VERSION 5.7 ;
NAMESCASESENSITIVE ON ;
BUSBITCHARS "[]" ;
DIVIDERCHAR "|" ;

PROPERTYDEFINITIONS
    LAYER LEF58_TYPE STRING ;
END PROPERTYDEFINITIONS


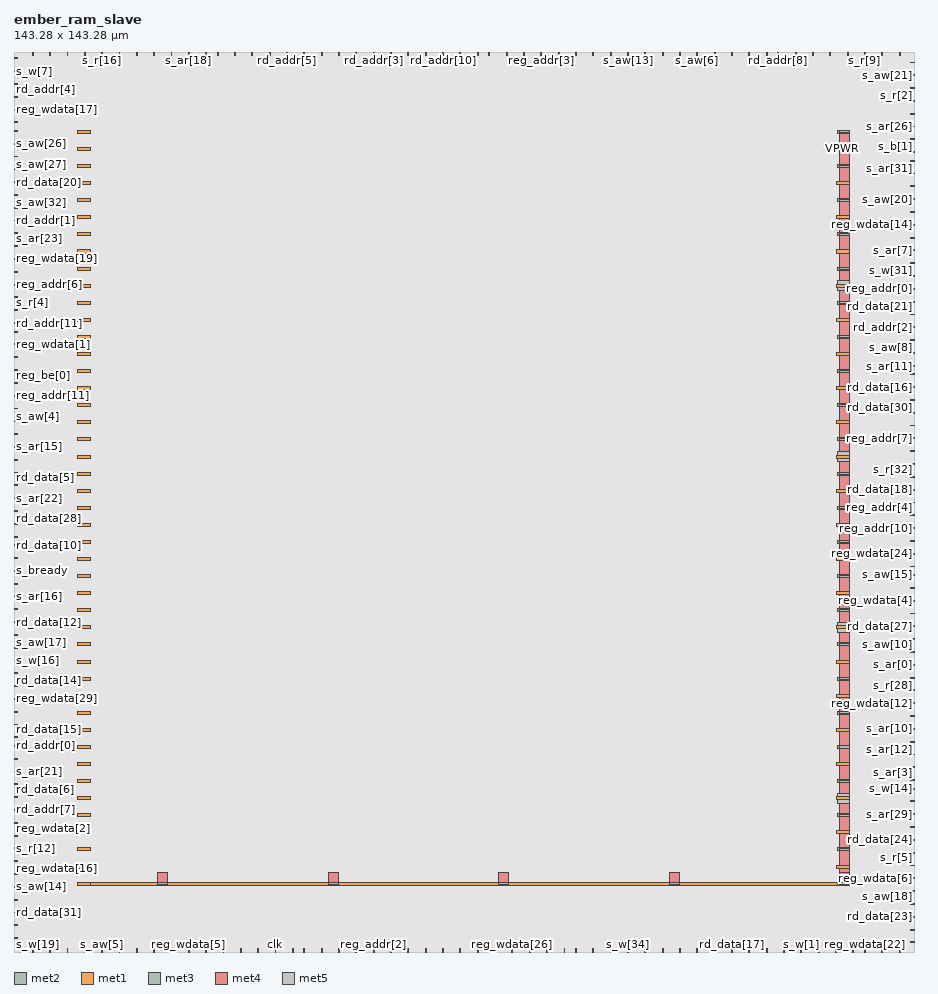
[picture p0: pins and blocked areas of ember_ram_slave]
MACRO ember_ram_slave
    CLASS BLOCK ;
    SIZE 143.28 BY 143.28 ;
    SYMMETRY Y ;
    PIN clk
        DIRECTION INPUT ; 
        USE SIGNAL ; 
        PORT
            LAYER met2 ;
              RECT  41.56 0 41.7 0.485 ;
        END
    END clk
    PIN rd_addr[0]
        DIRECTION OUTPUT ; 
        USE SIGNAL ; 
        PORT
            LAYER met1 ;
              RECT  0 32.74 0.595 32.88 ;
        END
    END rd_addr[0]
    PIN rd_addr[10]
        DIRECTION OUTPUT ; 
        USE SIGNAL ; 
        PORT
            LAYER met2 ;
              RECT  68.24 142.795 68.38 143.28 ;
        END
    END rd_addr[10]
    PIN rd_addr[11]
        DIRECTION OUTPUT ; 
        USE SIGNAL ; 
        PORT
            LAYER met1 ;
              RECT  0 100.06 0.595 100.2 ;
        END
    END rd_addr[11]
    PIN rd_addr[1]
        DIRECTION OUTPUT ; 
        USE SIGNAL ; 
        PORT
            LAYER met1 ;
              RECT  0 116.38 0.595 116.52 ;
        END
    END rd_addr[1]
    PIN rd_addr[2]
        DIRECTION OUTPUT ; 
        USE SIGNAL ; 
        PORT
            LAYER met1 ;
              RECT  142.685 99.38 143.28 99.52 ;
        END
    END rd_addr[2]
    PIN rd_addr[3]
        DIRECTION OUTPUT ; 
        USE SIGNAL ; 
        PORT
            LAYER met2 ;
              RECT  57.2 142.795 57.34 143.28 ;
        END
    END rd_addr[3]
    PIN rd_addr[4]
        DIRECTION OUTPUT ; 
        USE SIGNAL ; 
        PORT
            LAYER met1 ;
              RECT  0 136.1 0.595 136.24 ;
        END
    END rd_addr[4]
    PIN rd_addr[5]
        DIRECTION OUTPUT ; 
        USE SIGNAL ; 
        PORT
            LAYER met2 ;
              RECT  43.4 142.795 43.54 143.28 ;
        END
    END rd_addr[5]
    PIN rd_addr[6]
        DIRECTION OUTPUT ; 
        USE SIGNAL ; 
        PORT
            LAYER met1 ;
              RECT  142.685 141.54 143.28 141.68 ;
        END
    END rd_addr[6]
    PIN rd_addr[7]
        DIRECTION OUTPUT ; 
        USE SIGNAL ; 
        PORT
            LAYER met1 ;
              RECT  0 22.54 0.595 22.68 ;
        END
    END rd_addr[7]
    PIN rd_addr[8]
        DIRECTION OUTPUT ; 
        USE SIGNAL ; 
        PORT
            LAYER met2 ;
              RECT  121.6 142.795 121.74 143.28 ;
        END
    END rd_addr[8]
    PIN rd_addr[9]
        DIRECTION OUTPUT ; 
        USE SIGNAL ; 
        PORT
            LAYER met2 ;
              RECT  65.48 142.795 65.62 143.28 ;
        END
    END rd_addr[9]
    PIN rd_data[0]
        DIRECTION INPUT ; 
        USE SIGNAL ; 
        PORT
            LAYER met2 ;
              RECT  8.44 0 8.58 0.485 ;
        END
    END rd_data[0]
    PIN rd_data[10]
        DIRECTION INPUT ; 
        USE SIGNAL ; 
        PORT
            LAYER met1 ;
              RECT  0 64.7 0.595 64.84 ;
        END
    END rd_data[10]
    PIN rd_data[11]
        DIRECTION INPUT ; 
        USE SIGNAL ; 
        PORT
            LAYER met2 ;
              RECT  2.92 142.795 3.06 143.28 ;
        END
    END rd_data[11]
    PIN rd_data[12]
        DIRECTION INPUT ; 
        USE SIGNAL ; 
        PORT
            LAYER met1 ;
              RECT  0 52.46 0.595 52.6 ;
        END
    END rd_data[12]
    PIN rd_data[13]
        DIRECTION INPUT ; 
        USE SIGNAL ; 
        PORT
            LAYER met2 ;
              RECT  62.72 142.795 62.86 143.28 ;
        END
    END rd_data[13]
    PIN rd_data[14]
        DIRECTION INPUT ; 
        USE SIGNAL ; 
        PORT
            LAYER met1 ;
              RECT  0 44.3 0.595 44.44 ;
        END
    END rd_data[14]
    PIN rd_data[15]
        DIRECTION INPUT ; 
        USE SIGNAL ; 
        PORT
            LAYER met1 ;
              RECT  0 34.1 0.595 34.24 ;
        END
    END rd_data[15]
    PIN rd_data[16]
        DIRECTION INPUT ; 
        USE SIGNAL ; 
        PORT
            LAYER met1 ;
              RECT  142.685 89.86 143.28 90 ;
        END
    END rd_data[16]
    PIN rd_data[17]
        DIRECTION INPUT ; 
        USE SIGNAL ; 
        PORT
            LAYER met2 ;
              RECT  114.24 0 114.38 0.485 ;
        END
    END rd_data[17]
    PIN rd_data[18]
        DIRECTION INPUT ; 
        USE SIGNAL ; 
        PORT
            LAYER met1 ;
              RECT  142.685 73.54 143.28 73.68 ;
        END
    END rd_data[18]
    PIN rd_data[19]
        DIRECTION INPUT ; 
        USE SIGNAL ; 
        PORT
            LAYER met2 ;
              RECT  5.68 142.795 5.82 143.28 ;
        END
    END rd_data[19]
    PIN rd_data[1]
        DIRECTION INPUT ; 
        USE SIGNAL ; 
        PORT
            LAYER met2 ;
              RECT  78.36 142.795 78.5 143.28 ;
        END
    END rd_data[1]
    PIN rd_data[20]
        DIRECTION INPUT ; 
        USE SIGNAL ; 
        PORT
            LAYER met1 ;
              RECT  0 122.5 0.595 122.64 ;
        END
    END rd_data[20]
    PIN rd_data[21]
        DIRECTION INPUT ; 
        USE SIGNAL ; 
        PORT
            LAYER met1 ;
              RECT  142.685 101.42 143.28 101.56 ;
        END
    END rd_data[21]
    PIN rd_data[22]
        DIRECTION INPUT ; 
        USE SIGNAL ; 
        PORT
            LAYER met2 ;
              RECT  25 142.795 25.14 143.28 ;
        END
    END rd_data[22]
    PIN rd_data[23]
        DIRECTION INPUT ; 
        USE SIGNAL ; 
        PORT
            LAYER met1 ;
              RECT  142.685 5.54 143.28 5.68 ;
        END
    END rd_data[23]
    PIN rd_data[24]
        DIRECTION INPUT ; 
        USE SIGNAL ; 
        PORT
            LAYER met1 ;
              RECT  142.685 17.78 143.28 17.92 ;
        END
    END rd_data[24]
    PIN rd_data[25]
        DIRECTION INPUT ; 
        USE SIGNAL ; 
        PORT
            LAYER met2 ;
              RECT  32.36 142.795 32.5 143.28 ;
        END
    END rd_data[25]
    PIN rd_data[26]
        DIRECTION INPUT ; 
        USE SIGNAL ; 
        PORT
            LAYER met1 ;
              RECT  0 2.14 0.595 2.28 ;
        END
    END rd_data[26]
    PIN rd_data[27]
        DIRECTION INPUT ; 
        USE SIGNAL ; 
        PORT
            LAYER met1 ;
              RECT  142.685 51.78 143.28 51.92 ;
        END
    END rd_data[27]
    PIN rd_data[28]
        DIRECTION INPUT ; 
        USE SIGNAL ; 
        PORT
            LAYER met1 ;
              RECT  0 70.14 0.595 70.28 ;
        END
    END rd_data[28]
    PIN rd_data[29]
        DIRECTION INPUT ; 
        USE SIGNAL ; 
        PORT
            LAYER met1 ;
              RECT  142.685 9.62 143.28 9.76 ;
        END
    END rd_data[29]
    PIN rd_data[2]
        DIRECTION INPUT ; 
        USE SIGNAL ; 
        PORT
            LAYER met2 ;
              RECT  35.12 142.795 35.26 143.28 ;
        END
    END rd_data[2]
    PIN rd_data[30]
        DIRECTION INPUT ; 
        USE SIGNAL ; 
        PORT
            LAYER met1 ;
              RECT  142.685 87.82 143.28 87.96 ;
        END
    END rd_data[30]
    PIN rd_data[31]
        DIRECTION INPUT ; 
        USE SIGNAL ; 
        PORT
            LAYER met1 ;
              RECT  0 6.22 0.595 6.36 ;
        END
    END rd_data[31]
    PIN rd_data[3]
        DIRECTION INPUT ; 
        USE SIGNAL ; 
        PORT
            LAYER met2 ;
              RECT  94.92 0 95.06 0.485 ;
        END
    END rd_data[3]
    PIN rd_data[4]
        DIRECTION INPUT ; 
        USE SIGNAL ; 
        PORT
            LAYER met2 ;
              RECT  105.96 142.795 106.1 143.28 ;
        END
    END rd_data[4]
    PIN rd_data[5]
        DIRECTION INPUT ; 
        USE SIGNAL ; 
        PORT
            LAYER met1 ;
              RECT  0 74.22 0.595 74.36 ;
        END
    END rd_data[5]
    PIN rd_data[6]
        DIRECTION INPUT ; 
        USE SIGNAL ; 
        PORT
            LAYER met1 ;
              RECT  0 24.58 0.595 24.72 ;
        END
    END rd_data[6]
    PIN rd_data[7]
        DIRECTION INPUT ; 
        USE SIGNAL ; 
        PORT
            LAYER met1 ;
              RECT  0 26.62 0.595 26.76 ;
        END
    END rd_data[7]
    PIN rd_data[8]
        DIRECTION INPUT ; 
        USE SIGNAL ; 
        PORT
            LAYER met2 ;
              RECT  54.44 142.795 54.58 143.28 ;
        END
    END rd_data[8]
    PIN rd_data[9]
        DIRECTION INPUT ; 
        USE SIGNAL ; 
        PORT
            LAYER met1 ;
              RECT  142.685 127.26 143.28 127.4 ;
        END
    END rd_data[9]
    PIN reg_addr[0]
        DIRECTION OUTPUT ; 
        USE SIGNAL ; 
        PORT
            LAYER met1 ;
              RECT  142.685 105.5 143.28 105.64 ;
        END
    END reg_addr[0]
    PIN reg_addr[10]
        DIRECTION OUTPUT ; 
        USE SIGNAL ; 
        PORT
            LAYER met1 ;
              RECT  142.685 67.42 143.28 67.56 ;
        END
    END reg_addr[10]
    PIN reg_addr[11]
        DIRECTION OUTPUT ; 
        USE SIGNAL ; 
        PORT
            LAYER met1 ;
              RECT  0 88.5 0.595 88.64 ;
        END
    END reg_addr[11]
    PIN reg_addr[1]
        DIRECTION OUTPUT ; 
        USE SIGNAL ; 
        PORT
            LAYER met2 ;
              RECT  138.16 0 138.3 0.485 ;
        END
    END reg_addr[1]
    PIN reg_addr[2]
        DIRECTION OUTPUT ; 
        USE SIGNAL ; 
        PORT
            LAYER met2 ;
              RECT  57.2 0 57.34 0.485 ;
        END
    END reg_addr[2]
    PIN reg_addr[3]
        DIRECTION OUTPUT ; 
        USE SIGNAL ; 
        PORT
            LAYER met2 ;
              RECT  83.88 142.795 84.02 143.28 ;
        END
    END reg_addr[3]
    PIN reg_addr[4]
        DIRECTION OUTPUT ; 
        USE SIGNAL ; 
        PORT
            LAYER met1 ;
              RECT  142.685 69.46 143.28 69.6 ;
        END
    END reg_addr[4]
    PIN reg_addr[5]
        DIRECTION OUTPUT ; 
        USE SIGNAL ; 
        PORT
            LAYER met2 ;
              RECT  59.96 0 60.1 0.485 ;
        END
    END reg_addr[5]
    PIN reg_addr[6]
        DIRECTION OUTPUT ; 
        USE SIGNAL ; 
        PORT
            LAYER met1 ;
              RECT  0 106.18 0.595 106.32 ;
        END
    END reg_addr[6]
    PIN reg_addr[7]
        DIRECTION OUTPUT ; 
        USE SIGNAL ; 
        PORT
            LAYER met1 ;
              RECT  142.685 81.7 143.28 81.84 ;
        END
    END reg_addr[7]
    PIN reg_addr[8]
        DIRECTION OUTPUT ; 
        USE SIGNAL ; 
        PORT
            LAYER met2 ;
              RECT  8.44 142.795 8.58 143.28 ;
        END
    END reg_addr[8]
    PIN reg_addr[9]
        DIRECTION OUTPUT ; 
        USE SIGNAL ; 
        PORT
            LAYER met2 ;
              RECT  51.68 142.795 51.82 143.28 ;
        END
    END reg_addr[9]
    PIN reg_be[0]
        DIRECTION OUTPUT ; 
        USE SIGNAL ; 
        PORT
            LAYER met1 ;
              RECT  0 90.54 0.595 90.68 ;
        END
    END reg_be[0]
    PIN reg_be[1]
        DIRECTION OUTPUT ; 
        USE SIGNAL ; 
        PORT
            LAYER met2 ;
              RECT  132.64 142.795 132.78 143.28 ;
        END
    END reg_be[1]
    PIN reg_be[2]
        DIRECTION OUTPUT ; 
        USE SIGNAL ; 
        PORT
            LAYER met2 ;
              RECT  38.8 0 38.94 0.485 ;
        END
    END reg_be[2]
    PIN reg_be[3]
        DIRECTION OUTPUT ; 
        USE SIGNAL ; 
        PORT
            LAYER met2 ;
              RECT  92.16 0 92.3 0.485 ;
        END
    END reg_be[3]
    PIN reg_wdata[0]
        DIRECTION OUTPUT ; 
        USE SIGNAL ; 
        PORT
            LAYER met2 ;
              RECT  111.48 142.795 111.62 143.28 ;
        END
    END reg_wdata[0]
    PIN reg_wdata[10]
        DIRECTION OUTPUT ; 
        USE SIGNAL ; 
        PORT
            LAYER met2 ;
              RECT  128.04 0 128.18 0.485 ;
        END
    END reg_wdata[10]
    PIN reg_wdata[11]
        DIRECTION OUTPUT ; 
        USE SIGNAL ; 
        PORT
            LAYER met2 ;
              RECT  22.24 142.795 22.38 143.28 ;
        END
    END reg_wdata[11]
    PIN reg_wdata[12]
        DIRECTION OUTPUT ; 
        USE SIGNAL ; 
        PORT
            LAYER met1 ;
              RECT  142.685 39.54 143.28 39.68 ;
        END
    END reg_wdata[12]
    PIN reg_wdata[13]
        DIRECTION OUTPUT ; 
        USE SIGNAL ; 
        PORT
            LAYER met1 ;
              RECT  0 142.22 0.595 142.36 ;
        END
    END reg_wdata[13]
    PIN reg_wdata[14]
        DIRECTION OUTPUT ; 
        USE SIGNAL ; 
        PORT
            LAYER met1 ;
              RECT  142.685 115.7 143.28 115.84 ;
        END
    END reg_wdata[14]
    PIN reg_wdata[15]
        DIRECTION OUTPUT ; 
        USE SIGNAL ; 
        PORT
            LAYER met2 ;
              RECT  119.76 142.795 119.9 143.28 ;
        END
    END reg_wdata[15]
    PIN reg_wdata[16]
        DIRECTION OUTPUT ; 
        USE SIGNAL ; 
        PORT
            LAYER met1 ;
              RECT  0 14.38 0.595 14.52 ;
        END
    END reg_wdata[16]
    PIN reg_wdata[17]
        DIRECTION OUTPUT ; 
        USE SIGNAL ; 
        PORT
            LAYER met1 ;
              RECT  0 134.06 0.595 134.2 ;
        END
    END reg_wdata[17]
    PIN reg_wdata[18]
        DIRECTION OUTPUT ; 
        USE SIGNAL ; 
        PORT
            LAYER met2 ;
              RECT  46.16 142.795 46.3 143.28 ;
        END
    END reg_wdata[18]
    PIN reg_wdata[19]
        DIRECTION OUTPUT ; 
        USE SIGNAL ; 
        PORT
            LAYER met1 ;
              RECT  0 110.26 0.595 110.4 ;
        END
    END reg_wdata[19]
    PIN reg_wdata[1]
        DIRECTION OUTPUT ; 
        USE SIGNAL ; 
        PORT
            LAYER met1 ;
              RECT  0 96.66 0.595 96.8 ;
        END
    END reg_wdata[1]
    PIN reg_wdata[20]
        DIRECTION OUTPUT ; 
        USE SIGNAL ; 
        PORT
            LAYER met1 ;
              RECT  142.685 135.42 143.28 135.56 ;
        END
    END reg_wdata[20]
    PIN reg_wdata[21]
        DIRECTION OUTPUT ; 
        USE SIGNAL ; 
        PORT
            LAYER met1 ;
              RECT  142.685 3.5 143.28 3.64 ;
        END
    END reg_wdata[21]
    PIN reg_wdata[22]
        DIRECTION OUTPUT ; 
        USE SIGNAL ; 
        PORT
            LAYER met2 ;
              RECT  135.4 0 135.54 0.485 ;
        END
    END reg_wdata[22]
    PIN reg_wdata[23]
        DIRECTION OUTPUT ; 
        USE SIGNAL ; 
        PORT
            LAYER met2 ;
              RECT  68.24 0 68.38 0.485 ;
        END
    END reg_wdata[23]
    PIN reg_wdata[24]
        DIRECTION OUTPUT ; 
        USE SIGNAL ; 
        PORT
            LAYER met1 ;
              RECT  142.685 63.34 143.28 63.48 ;
        END
    END reg_wdata[24]
    PIN reg_wdata[25]
        DIRECTION OUTPUT ; 
        USE SIGNAL ; 
        PORT
            LAYER met2 ;
              RECT  65.48 0 65.62 0.485 ;
        END
    END reg_wdata[25]
    PIN reg_wdata[26]
        DIRECTION OUTPUT ; 
        USE SIGNAL ; 
        PORT
            LAYER met2 ;
              RECT  79.28 0 79.42 0.485 ;
        END
    END reg_wdata[26]
    PIN reg_wdata[27]
        DIRECTION OUTPUT ; 
        USE SIGNAL ; 
        PORT
            LAYER met1 ;
              RECT  0 68.1 0.595 68.24 ;
        END
    END reg_wdata[27]
    PIN reg_wdata[28]
        DIRECTION OUTPUT ; 
        USE SIGNAL ; 
        PORT
            LAYER met2 ;
              RECT  19.48 0 19.62 0.485 ;
        END
    END reg_wdata[28]
    PIN reg_wdata[29]
        DIRECTION OUTPUT ; 
        USE SIGNAL ; 
        PORT
            LAYER met1 ;
              RECT  0 40.22 0.595 40.36 ;
        END
    END reg_wdata[29]
    PIN reg_wdata[2]
        DIRECTION OUTPUT ; 
        USE SIGNAL ; 
        PORT
            LAYER met1 ;
              RECT  0 18.46 0.595 18.6 ;
        END
    END reg_wdata[2]
    PIN reg_wdata[30]
        DIRECTION OUTPUT ; 
        USE SIGNAL ; 
        PORT
            LAYER met2 ;
              RECT  140.92 0 141.06 0.485 ;
        END
    END reg_wdata[30]
    PIN reg_wdata[31]
        DIRECTION OUTPUT ; 
        USE SIGNAL ; 
        PORT
            LAYER met2 ;
              RECT  138.16 142.795 138.3 143.28 ;
        END
    END reg_wdata[31]
    PIN reg_wdata[3]
        DIRECTION OUTPUT ; 
        USE SIGNAL ; 
        PORT
            LAYER met1 ;
              RECT  142.685 85.78 143.28 85.92 ;
        END
    END reg_wdata[3]
    PIN reg_wdata[4]
        DIRECTION OUTPUT ; 
        USE SIGNAL ; 
        PORT
            LAYER met1 ;
              RECT  142.685 55.86 143.28 56 ;
        END
    END reg_wdata[4]
    PIN reg_wdata[5]
        DIRECTION OUTPUT ; 
        USE SIGNAL ; 
        PORT
            LAYER met2 ;
              RECT  27.76 0 27.9 0.485 ;
        END
    END reg_wdata[5]
    PIN reg_wdata[6]
        DIRECTION OUTPUT ; 
        USE SIGNAL ; 
        PORT
            LAYER met1 ;
              RECT  142.685 11.66 143.28 11.8 ;
        END
    END reg_wdata[6]
    PIN reg_wdata[7]
        DIRECTION OUTPUT ; 
        USE SIGNAL ; 
        PORT
            LAYER met1 ;
              RECT  142.685 133.38 143.28 133.52 ;
        END
    END reg_wdata[7]
    PIN reg_wdata[8]
        DIRECTION OUTPUT ; 
        USE SIGNAL ; 
        PORT
            LAYER met2 ;
              RECT  73.76 142.795 73.9 143.28 ;
        END
    END reg_wdata[8]
    PIN reg_wdata[9]
        DIRECTION OUTPUT ; 
        USE SIGNAL ; 
        PORT
            LAYER met2 ;
              RECT  16.72 0 16.86 0.485 ;
        END
    END reg_wdata[9]
    PIN reg_wr_en
        DIRECTION OUTPUT ; 
        USE SIGNAL ; 
        PORT
            LAYER met2 ;
              RECT  94.92 142.795 95.06 143.28 ;
        END
    END reg_wr_en
    PIN rst_n
        DIRECTION INPUT ; 
        USE SIGNAL ; 
        PORT
            LAYER met1 ;
              RECT  0 94.62 0.595 94.76 ;
        END
    END rst_n
    PIN s_ar[0]
        DIRECTION INPUT ; 
        USE SIGNAL ; 
        PORT
            LAYER met1 ;
              RECT  142.685 45.66 143.28 45.8 ;
        END
    END s_ar[0]
    PIN s_ar[10]
        DIRECTION INPUT ; 
        USE SIGNAL ; 
        PORT
            LAYER met1 ;
              RECT  142.685 35.46 143.28 35.6 ;
        END
    END s_ar[10]
    PIN s_ar[11]
        DIRECTION INPUT ; 
        USE SIGNAL ; 
        PORT
            LAYER met1 ;
              RECT  142.685 91.9 143.28 92.04 ;
        END
    END s_ar[11]
    PIN s_ar[12]
        DIRECTION INPUT ; 
        USE SIGNAL ; 
        PORT
            LAYER met1 ;
              RECT  142.685 33.42 143.28 33.56 ;
        END
    END s_ar[12]
    PIN s_ar[13]
        DIRECTION INPUT ; 
        USE SIGNAL ; 
        PORT
            LAYER met2 ;
              RECT  51.68 0 51.82 0.485 ;
        END
    END s_ar[13]
    PIN s_ar[14]
        DIRECTION INPUT ; 
        USE SIGNAL ; 
        PORT
            LAYER met1 ;
              RECT  0 20.5 0.595 20.64 ;
        END
    END s_ar[14]
    PIN s_ar[15]
        DIRECTION INPUT ; 
        USE SIGNAL ; 
        PORT
            LAYER met1 ;
              RECT  0 80.34 0.595 80.48 ;
        END
    END s_ar[15]
    PIN s_ar[16]
        DIRECTION INPUT ; 
        USE SIGNAL ; 
        PORT
            LAYER met1 ;
              RECT  0 56.54 0.595 56.68 ;
        END
    END s_ar[16]
    PIN s_ar[17]
        DIRECTION INPUT ; 
        USE SIGNAL ; 
        PORT
            LAYER met2 ;
              RECT  82.04 0 82.18 0.485 ;
        END
    END s_ar[17]
    PIN s_ar[18]
        DIRECTION INPUT ; 
        USE SIGNAL ; 
        PORT
            LAYER met2 ;
              RECT  27.76 142.795 27.9 143.28 ;
        END
    END s_ar[18]
    PIN s_ar[19]
        DIRECTION INPUT ; 
        USE SIGNAL ; 
        PORT
            LAYER met2 ;
              RECT  129.88 142.795 130.02 143.28 ;
        END
    END s_ar[19]
    PIN s_ar[1]
        DIRECTION INPUT ; 
        USE SIGNAL ; 
        PORT
            LAYER met2 ;
              RECT  71 142.795 71.14 143.28 ;
        END
    END s_ar[1]
    PIN s_ar[20]
        DIRECTION INPUT ; 
        USE SIGNAL ; 
        PORT
            LAYER met2 ;
              RECT  122.52 0 122.66 0.485 ;
        END
    END s_ar[20]
    PIN s_ar[21]
        DIRECTION INPUT ; 
        USE SIGNAL ; 
        PORT
            LAYER met1 ;
              RECT  0 28.66 0.595 28.8 ;
        END
    END s_ar[21]
    PIN s_ar[22]
        DIRECTION INPUT ; 
        USE SIGNAL ; 
        PORT
            LAYER met1 ;
              RECT  0 72.18 0.595 72.32 ;
        END
    END s_ar[22]
    PIN s_ar[23]
        DIRECTION INPUT ; 
        USE SIGNAL ; 
        PORT
            LAYER met1 ;
              RECT  0 112.3 0.595 112.44 ;
        END
    END s_ar[23]
    PIN s_ar[24]
        DIRECTION INPUT ; 
        USE SIGNAL ; 
        PORT
            LAYER met2 ;
              RECT  48.92 0 49.06 0.485 ;
        END
    END s_ar[24]
    PIN s_ar[25]
        DIRECTION INPUT ; 
        USE SIGNAL ; 
        PORT
            LAYER met1 ;
              RECT  0 98.7 0.595 98.84 ;
        END
    END s_ar[25]
    PIN s_ar[26]
        DIRECTION INPUT ; 
        USE SIGNAL ; 
        PORT
            LAYER met1 ;
              RECT  142.685 131.34 143.28 131.48 ;
        END
    END s_ar[26]
    PIN s_ar[27]
        DIRECTION INPUT ; 
        USE SIGNAL ; 
        PORT
            LAYER met1 ;
              RECT  0 138.14 0.595 138.28 ;
        END
    END s_ar[27]
    PIN s_ar[28]
        DIRECTION INPUT ; 
        USE SIGNAL ; 
        PORT
            LAYER met1 ;
              RECT  0 36.14 0.595 36.28 ;
        END
    END s_ar[28]
    PIN s_ar[29]
        DIRECTION INPUT ; 
        USE SIGNAL ; 
        PORT
            LAYER met1 ;
              RECT  142.685 21.86 143.28 22 ;
        END
    END s_ar[29]
    PIN s_ar[2]
        DIRECTION INPUT ; 
        USE SIGNAL ; 
        PORT
            LAYER met1 ;
              RECT  0 4.18 0.595 4.32 ;
        END
    END s_ar[2]
    PIN s_ar[30]
        DIRECTION INPUT ; 
        USE SIGNAL ; 
        PORT
            LAYER met2 ;
              RECT  100.44 142.795 100.58 143.28 ;
        END
    END s_ar[30]
    PIN s_ar[31]
        DIRECTION INPUT ; 
        USE SIGNAL ; 
        PORT
            LAYER met1 ;
              RECT  142.685 125.9 143.28 126.04 ;
        END
    END s_ar[31]
    PIN s_ar[32]
        DIRECTION INPUT ; 
        USE SIGNAL ; 
        PORT
            LAYER met2 ;
              RECT  117 0 117.14 0.485 ;
        END
    END s_ar[32]
    PIN s_ar[33]
        DIRECTION INPUT ; 
        USE SIGNAL ; 
        PORT
            LAYER met1 ;
              RECT  142.685 37.5 143.28 37.64 ;
        END
    END s_ar[33]
    PIN s_ar[34]
        DIRECTION INPUT ; 
        USE SIGNAL ; 
        PORT
            LAYER met2 ;
              RECT  30.52 142.795 30.66 143.28 ;
        END
    END s_ar[34]
    PIN s_ar[3]
        DIRECTION INPUT ; 
        USE SIGNAL ; 
        PORT
            LAYER met1 ;
              RECT  142.685 27.3 143.28 27.44 ;
        END
    END s_ar[3]
    PIN s_ar[4]
        DIRECTION INPUT ; 
        USE SIGNAL ; 
        PORT
            LAYER met2 ;
              RECT  89.4 0 89.54 0.485 ;
        END
    END s_ar[4]
    PIN s_ar[5]
        DIRECTION INPUT ; 
        USE SIGNAL ; 
        PORT
            LAYER met1 ;
              RECT  142.685 83.74 143.28 83.88 ;
        END
    END s_ar[5]
    PIN s_ar[6]
        DIRECTION INPUT ; 
        USE SIGNAL ; 
        PORT
            LAYER met2 ;
              RECT  133.56 0 133.7 0.485 ;
        END
    END s_ar[6]
    PIN s_ar[7]
        DIRECTION INPUT ; 
        USE SIGNAL ; 
        PORT
            LAYER met1 ;
              RECT  142.685 111.62 143.28 111.76 ;
        END
    END s_ar[7]
    PIN s_ar[8]
        DIRECTION INPUT ; 
        USE SIGNAL ; 
        PORT
            LAYER met2 ;
              RECT  48.92 142.795 49.06 143.28 ;
        END
    END s_ar[8]
    PIN s_ar[9]
        DIRECTION INPUT ; 
        USE SIGNAL ; 
        PORT
            LAYER met2 ;
              RECT  140.92 142.795 141.06 143.28 ;
        END
    END s_ar[9]
    PIN s_arready
        DIRECTION OUTPUT ; 
        USE SIGNAL ; 
        PORT
            LAYER met1 ;
              RECT  0 38.18 0.595 38.32 ;
        END
    END s_arready
    PIN s_arvalid
        DIRECTION INPUT ; 
        USE SIGNAL ; 
        PORT
            LAYER met1 ;
              RECT  142.685 31.38 143.28 31.52 ;
        END
    END s_arvalid
    PIN s_aw[0]
        DIRECTION INPUT ; 
        USE SIGNAL ; 
        PORT
            LAYER met2 ;
              RECT  71 0 71.14 0.485 ;
        END
    END s_aw[0]
    PIN s_aw[10]
        DIRECTION INPUT ; 
        USE SIGNAL ; 
        PORT
            LAYER met1 ;
              RECT  142.685 47.7 143.28 47.84 ;
        END
    END s_aw[10]
    PIN s_aw[11]
        DIRECTION INPUT ; 
        USE SIGNAL ; 
        PORT
            LAYER met1 ;
              RECT  0 130.66 0.595 130.8 ;
        END
    END s_aw[11]
    PIN s_aw[12]
        DIRECTION INPUT ; 
        USE SIGNAL ; 
        PORT
            LAYER met1 ;
              RECT  0 8.26 0.595 8.4 ;
        END
    END s_aw[12]
    PIN s_aw[13]
        DIRECTION INPUT ; 
        USE SIGNAL ; 
        PORT
            LAYER met2 ;
              RECT  97.68 142.795 97.82 143.28 ;
        END
    END s_aw[13]
    PIN s_aw[14]
        DIRECTION INPUT ; 
        USE SIGNAL ; 
        PORT
            LAYER met1 ;
              RECT  0 10.3 0.595 10.44 ;
        END
    END s_aw[14]
    PIN s_aw[15]
        DIRECTION INPUT ; 
        USE SIGNAL ; 
        PORT
            LAYER met1 ;
              RECT  142.685 61.3 143.28 61.44 ;
        END
    END s_aw[15]
    PIN s_aw[16]
        DIRECTION INPUT ; 
        USE SIGNAL ; 
        PORT
            LAYER met2 ;
              RECT  127.12 142.795 127.26 143.28 ;
        END
    END s_aw[16]
    PIN s_aw[17]
        DIRECTION INPUT ; 
        USE SIGNAL ; 
        PORT
            LAYER met1 ;
              RECT  0 50.42 0.595 50.56 ;
        END
    END s_aw[17]
    PIN s_aw[18]
        DIRECTION INPUT ; 
        USE SIGNAL ; 
        PORT
            LAYER met1 ;
              RECT  142.685 7.58 143.28 7.72 ;
        END
    END s_aw[18]
    PIN s_aw[19]
        DIRECTION INPUT ; 
        USE SIGNAL ; 
        PORT
            LAYER met2 ;
              RECT  114.24 142.795 114.38 143.28 ;
        END
    END s_aw[19]
    PIN s_aw[1]
        DIRECTION INPUT ; 
        USE SIGNAL ; 
        PORT
            LAYER met1 ;
              RECT  142.685 23.9 143.28 24.04 ;
        END
    END s_aw[1]
    PIN s_aw[20]
        DIRECTION INPUT ; 
        USE SIGNAL ; 
        PORT
            LAYER met1 ;
              RECT  142.685 119.78 143.28 119.92 ;
        END
    END s_aw[20]
    PIN s_aw[21]
        DIRECTION INPUT ; 
        USE SIGNAL ; 
        PORT
            LAYER met1 ;
              RECT  142.685 139.5 143.28 139.64 ;
        END
    END s_aw[21]
    PIN s_aw[22]
        DIRECTION INPUT ; 
        USE SIGNAL ; 
        PORT
            LAYER met2 ;
              RECT  92.16 142.795 92.3 143.28 ;
        END
    END s_aw[22]
    PIN s_aw[23]
        DIRECTION INPUT ; 
        USE SIGNAL ; 
        PORT
            LAYER met1 ;
              RECT  0 76.26 0.595 76.4 ;
        END
    END s_aw[23]
    PIN s_aw[24]
        DIRECTION INPUT ; 
        USE SIGNAL ; 
        PORT
            LAYER met2 ;
              RECT  73.76 0 73.9 0.485 ;
        END
    END s_aw[24]
    PIN s_aw[25]
        DIRECTION INPUT ; 
        USE SIGNAL ; 
        PORT
            LAYER met1 ;
              RECT  142.685 65.38 143.28 65.52 ;
        END
    END s_aw[25]
    PIN s_aw[26]
        DIRECTION INPUT ; 
        USE SIGNAL ; 
        PORT
            LAYER met1 ;
              RECT  0 128.62 0.595 128.76 ;
        END
    END s_aw[26]
    PIN s_aw[27]
        DIRECTION INPUT ; 
        USE SIGNAL ; 
        PORT
            LAYER met1 ;
              RECT  0 126.58 0.595 126.72 ;
        END
    END s_aw[27]
    PIN s_aw[28]
        DIRECTION INPUT ; 
        USE SIGNAL ; 
        PORT
            LAYER met1 ;
              RECT  142.685 53.82 143.28 53.96 ;
        END
    END s_aw[28]
    PIN s_aw[29]
        DIRECTION INPUT ; 
        USE SIGNAL ; 
        PORT
            LAYER met1 ;
              RECT  0 66.06 0.595 66.2 ;
        END
    END s_aw[29]
    PIN s_aw[2]
        DIRECTION INPUT ; 
        USE SIGNAL ; 
        PORT
            LAYER met2 ;
              RECT  130.8 0 130.94 0.485 ;
        END
    END s_aw[2]
    PIN s_aw[30]
        DIRECTION INPUT ; 
        USE SIGNAL ; 
        PORT
            LAYER met2 ;
              RECT  16.72 142.795 16.86 143.28 ;
        END
    END s_aw[30]
    PIN s_aw[31]
        DIRECTION INPUT ; 
        USE SIGNAL ; 
        PORT
            LAYER met1 ;
              RECT  142.685 103.46 143.28 103.6 ;
        END
    END s_aw[31]
    PIN s_aw[32]
        DIRECTION INPUT ; 
        USE SIGNAL ; 
        PORT
            LAYER met1 ;
              RECT  0 120.46 0.595 120.6 ;
        END
    END s_aw[32]
    PIN s_aw[33]
        DIRECTION INPUT ; 
        USE SIGNAL ; 
        PORT
            LAYER met2 ;
              RECT  111.48 0 111.62 0.485 ;
        END
    END s_aw[33]
    PIN s_aw[34]
        DIRECTION INPUT ; 
        USE SIGNAL ; 
        PORT
            LAYER met1 ;
              RECT  142.685 19.82 143.28 19.96 ;
        END
    END s_aw[34]
    PIN s_aw[3]
        DIRECTION INPUT ; 
        USE SIGNAL ; 
        PORT
            LAYER met2 ;
              RECT  81.12 142.795 81.26 143.28 ;
        END
    END s_aw[3]
    PIN s_aw[4]
        DIRECTION INPUT ; 
        USE SIGNAL ; 
        PORT
            LAYER met1 ;
              RECT  0 86.46 0.595 86.6 ;
        END
    END s_aw[4]
    PIN s_aw[5]
        DIRECTION INPUT ; 
        USE SIGNAL ; 
        PORT
            LAYER met2 ;
              RECT  13.96 0 14.1 0.485 ;
        END
    END s_aw[5]
    PIN s_aw[6]
        DIRECTION INPUT ; 
        USE SIGNAL ; 
        PORT
            LAYER met2 ;
              RECT  108.72 142.795 108.86 143.28 ;
        END
    END s_aw[6]
    PIN s_aw[7]
        DIRECTION INPUT ; 
        USE SIGNAL ; 
        PORT
            LAYER met1 ;
              RECT  142.685 57.9 143.28 58.04 ;
        END
    END s_aw[7]
    PIN s_aw[8]
        DIRECTION INPUT ; 
        USE SIGNAL ; 
        PORT
            LAYER met1 ;
              RECT  142.685 97.34 143.28 97.48 ;
        END
    END s_aw[8]
    PIN s_aw[9]
        DIRECTION INPUT ; 
        USE SIGNAL ; 
        PORT
            LAYER met2 ;
              RECT  54.44 0 54.58 0.485 ;
        END
    END s_aw[9]
    PIN s_awready
        DIRECTION OUTPUT ; 
        USE SIGNAL ; 
        PORT
            LAYER met1 ;
              RECT  142.685 123.86 143.28 124 ;
        END
    END s_awready
    PIN s_awvalid
        DIRECTION INPUT ; 
        USE SIGNAL ; 
        PORT
            LAYER met1 ;
              RECT  0 108.22 0.595 108.36 ;
        END
    END s_awvalid
    PIN s_b[0]
        DIRECTION OUTPUT ; 
        USE SIGNAL ; 
        PORT
            LAYER met2 ;
              RECT  108.72 0 108.86 0.485 ;
        END
    END s_b[0]
    PIN s_b[1]
        DIRECTION OUTPUT ; 
        USE SIGNAL ; 
        PORT
            LAYER met1 ;
              RECT  142.685 129.3 143.28 129.44 ;
        END
    END s_b[1]
    PIN s_bready
        DIRECTION INPUT ; 
        USE SIGNAL ; 
        PORT
            LAYER met1 ;
              RECT  0 60.62 0.595 60.76 ;
        END
    END s_bready
    PIN s_bvalid
        DIRECTION OUTPUT ; 
        USE SIGNAL ; 
        PORT
            LAYER met2 ;
              RECT  44.32 0 44.46 0.485 ;
        END
    END s_bvalid
    PIN s_r[0]
        DIRECTION OUTPUT ; 
        USE SIGNAL ; 
        PORT
            LAYER met1 ;
              RECT  0 132.02 0.595 132.16 ;
        END
    END s_r[0]
    PIN s_r[10]
        DIRECTION OUTPUT ; 
        USE SIGNAL ; 
        PORT
            LAYER met1 ;
              RECT  142.685 1.46 143.28 1.6 ;
        END
    END s_r[10]
    PIN s_r[11]
        DIRECTION OUTPUT ; 
        USE SIGNAL ; 
        PORT
            LAYER met1 ;
              RECT  142.685 29.34 143.28 29.48 ;
        END
    END s_r[11]
    PIN s_r[12]
        DIRECTION OUTPUT ; 
        USE SIGNAL ; 
        PORT
            LAYER met1 ;
              RECT  0 16.42 0.595 16.56 ;
        END
    END s_r[12]
    PIN s_r[13]
        DIRECTION OUTPUT ; 
        USE SIGNAL ; 
        PORT
            LAYER met1 ;
              RECT  142.685 95.3 143.28 95.44 ;
        END
    END s_r[13]
    PIN s_r[14]
        DIRECTION OUTPUT ; 
        USE SIGNAL ; 
        PORT
            LAYER met2 ;
              RECT  11.2 142.795 11.34 143.28 ;
        END
    END s_r[14]
    PIN s_r[15]
        DIRECTION OUTPUT ; 
        USE SIGNAL ; 
        PORT
            LAYER met2 ;
              RECT  19.48 142.795 19.62 143.28 ;
        END
    END s_r[15]
    PIN s_r[16]
        DIRECTION OUTPUT ; 
        USE SIGNAL ; 
        PORT
            LAYER met2 ;
              RECT  13.96 142.795 14.1 143.28 ;
        END
    END s_r[16]
    PIN s_r[17]
        DIRECTION OUTPUT ; 
        USE SIGNAL ; 
        PORT
            LAYER met2 ;
              RECT  5.68 0 5.82 0.485 ;
        END
    END s_r[17]
    PIN s_r[18]
        DIRECTION OUTPUT ; 
        USE SIGNAL ; 
        PORT
            LAYER met2 ;
              RECT  30.52 0 30.66 0.485 ;
        END
    END s_r[18]
    PIN s_r[19]
        DIRECTION OUTPUT ; 
        USE SIGNAL ; 
        PORT
            LAYER met1 ;
              RECT  0 84.42 0.595 84.56 ;
        END
    END s_r[19]
    PIN s_r[1]
        DIRECTION OUTPUT ; 
        USE SIGNAL ; 
        PORT
            LAYER met2 ;
              RECT  84.8 0 84.94 0.485 ;
        END
    END s_r[1]
    PIN s_r[20]
        DIRECTION OUTPUT ; 
        USE SIGNAL ; 
        PORT
            LAYER met1 ;
              RECT  0 82.38 0.595 82.52 ;
        END
    END s_r[20]
    PIN s_r[21]
        DIRECTION OUTPUT ; 
        USE SIGNAL ; 
        PORT
            LAYER met1 ;
              RECT  0 114.34 0.595 114.48 ;
        END
    END s_r[21]
    PIN s_r[22]
        DIRECTION OUTPUT ; 
        USE SIGNAL ; 
        PORT
            LAYER met1 ;
              RECT  0 48.38 0.595 48.52 ;
        END
    END s_r[22]
    PIN s_r[23]
        DIRECTION OUTPUT ; 
        USE SIGNAL ; 
        PORT
            LAYER met2 ;
              RECT  22.24 0 22.38 0.485 ;
        END
    END s_r[23]
    PIN s_r[24]
        DIRECTION OUTPUT ; 
        USE SIGNAL ; 
        PORT
            LAYER met1 ;
              RECT  142.685 71.5 143.28 71.64 ;
        END
    END s_r[24]
    PIN s_r[25]
        DIRECTION OUTPUT ; 
        USE SIGNAL ; 
        PORT
            LAYER met1 ;
              RECT  142.685 121.82 143.28 121.96 ;
        END
    END s_r[25]
    PIN s_r[26]
        DIRECTION OUTPUT ; 
        USE SIGNAL ; 
        PORT
            LAYER met1 ;
              RECT  0 12.34 0.595 12.48 ;
        END
    END s_r[26]
    PIN s_r[27]
        DIRECTION OUTPUT ; 
        USE SIGNAL ; 
        PORT
            LAYER met1 ;
              RECT  142.685 93.26 143.28 93.4 ;
        END
    END s_r[27]
    PIN s_r[28]
        DIRECTION OUTPUT ; 
        USE SIGNAL ; 
        PORT
            LAYER met1 ;
              RECT  142.685 43.62 143.28 43.76 ;
        END
    END s_r[28]
    PIN s_r[29]
        DIRECTION OUTPUT ; 
        USE SIGNAL ; 
        PORT
            LAYER met2 ;
              RECT  103.2 0 103.34 0.485 ;
        END
    END s_r[29]
    PIN s_r[2]
        DIRECTION OUTPUT ; 
        USE SIGNAL ; 
        PORT
            LAYER met1 ;
              RECT  142.685 137.46 143.28 137.6 ;
        END
    END s_r[2]
    PIN s_r[30]
        DIRECTION OUTPUT ; 
        USE SIGNAL ; 
        PORT
            LAYER met2 ;
              RECT  59.96 142.795 60.1 143.28 ;
        END
    END s_r[30]
    PIN s_r[31]
        DIRECTION OUTPUT ; 
        USE SIGNAL ; 
        PORT
            LAYER met2 ;
              RECT  46.16 0 46.3 0.485 ;
        END
    END s_r[31]
    PIN s_r[32]
        DIRECTION OUTPUT ; 
        USE SIGNAL ; 
        PORT
            LAYER met1 ;
              RECT  142.685 75.58 143.28 75.72 ;
        END
    END s_r[32]
    PIN s_r[33]
        DIRECTION OUTPUT ; 
        USE SIGNAL ; 
        PORT
            LAYER met1 ;
              RECT  0 54.5 0.595 54.64 ;
        END
    END s_r[33]
    PIN s_r[3]
        DIRECTION OUTPUT ; 
        USE SIGNAL ; 
        PORT
            LAYER met1 ;
              RECT  142.685 41.58 143.28 41.72 ;
        END
    END s_r[3]
    PIN s_r[4]
        DIRECTION OUTPUT ; 
        USE SIGNAL ; 
        PORT
            LAYER met1 ;
              RECT  0 102.1 0.595 102.24 ;
        END
    END s_r[4]
    PIN s_r[5]
        DIRECTION OUTPUT ; 
        USE SIGNAL ; 
        PORT
            LAYER met1 ;
              RECT  142.685 13.7 143.28 13.84 ;
        END
    END s_r[5]
    PIN s_r[6]
        DIRECTION OUTPUT ; 
        USE SIGNAL ; 
        PORT
            LAYER met2 ;
              RECT  25 0 25.14 0.485 ;
        END
    END s_r[6]
    PIN s_r[7]
        DIRECTION OUTPUT ; 
        USE SIGNAL ; 
        PORT
            LAYER met2 ;
              RECT  76.52 0 76.66 0.485 ;
        END
    END s_r[7]
    PIN s_r[8]
        DIRECTION OUTPUT ; 
        USE SIGNAL ; 
        PORT
            LAYER met1 ;
              RECT  142.685 59.94 143.28 60.08 ;
        END
    END s_r[8]
    PIN s_r[9]
        DIRECTION OUTPUT ; 
        USE SIGNAL ; 
        PORT
            LAYER met2 ;
              RECT  135.4 142.795 135.54 143.28 ;
        END
    END s_r[9]
    PIN s_rready
        DIRECTION INPUT ; 
        USE SIGNAL ; 
        PORT
            LAYER met1 ;
              RECT  142.685 113.66 143.28 113.8 ;
        END
    END s_rready
    PIN s_rvalid
        DIRECTION OUTPUT ; 
        USE SIGNAL ; 
        PORT
            LAYER met1 ;
              RECT  142.685 15.74 143.28 15.88 ;
        END
    END s_rvalid
    PIN s_w[0]
        DIRECTION INPUT ; 
        USE SIGNAL ; 
        PORT
            LAYER met1 ;
              RECT  0 42.26 0.595 42.4 ;
        END
    END s_w[0]
    PIN s_w[10]
        DIRECTION INPUT ; 
        USE SIGNAL ; 
        PORT
            LAYER met1 ;
              RECT  142.685 77.62 143.28 77.76 ;
        END
    END s_w[10]
    PIN s_w[11]
        DIRECTION INPUT ; 
        USE SIGNAL ; 
        PORT
            LAYER met2 ;
              RECT  2.92 0 3.06 0.485 ;
        END
    END s_w[11]
    PIN s_w[12]
        DIRECTION INPUT ; 
        USE SIGNAL ; 
        PORT
            LAYER met1 ;
              RECT  142.685 117.74 143.28 117.88 ;
        END
    END s_w[12]
    PIN s_w[13]
        DIRECTION INPUT ; 
        USE SIGNAL ; 
        PORT
            LAYER met2 ;
              RECT  124.36 142.795 124.5 143.28 ;
        END
    END s_w[13]
    PIN s_w[14]
        DIRECTION INPUT ; 
        USE SIGNAL ; 
        PORT
            LAYER met1 ;
              RECT  142.685 25.94 143.28 26.08 ;
        END
    END s_w[14]
    PIN s_w[15]
        DIRECTION INPUT ; 
        USE SIGNAL ; 
        PORT
            LAYER met2 ;
              RECT  117 142.795 117.14 143.28 ;
        END
    END s_w[15]
    PIN s_w[16]
        DIRECTION INPUT ; 
        USE SIGNAL ; 
        PORT
            LAYER met1 ;
              RECT  0 46.34 0.595 46.48 ;
        END
    END s_w[16]
    PIN s_w[17]
        DIRECTION INPUT ; 
        USE SIGNAL ; 
        PORT
            LAYER met1 ;
              RECT  0 62.66 0.595 62.8 ;
        END
    END s_w[17]
    PIN s_w[18]
        DIRECTION INPUT ; 
        USE SIGNAL ; 
        PORT
            LAYER met2 ;
              RECT  105.96 0 106.1 0.485 ;
        END
    END s_w[18]
    PIN s_w[19]
        DIRECTION INPUT ; 
        USE SIGNAL ; 
        PORT
            LAYER met2 ;
              RECT  1.08 0 1.22 0.485 ;
        END
    END s_w[19]
    PIN s_w[1]
        DIRECTION INPUT ; 
        USE SIGNAL ; 
        PORT
            LAYER met2 ;
              RECT  125.28 0 125.42 0.485 ;
        END
    END s_w[1]
    PIN s_w[20]
        DIRECTION INPUT ; 
        USE SIGNAL ; 
        PORT
            LAYER met1 ;
              RECT  0 78.3 0.595 78.44 ;
        END
    END s_w[20]
    PIN s_w[21]
        DIRECTION INPUT ; 
        USE SIGNAL ; 
        PORT
            LAYER met1 ;
              RECT  0 124.54 0.595 124.68 ;
        END
    END s_w[21]
    PIN s_w[22]
        DIRECTION INPUT ; 
        USE SIGNAL ; 
        PORT
            LAYER met2 ;
              RECT  40.64 142.795 40.78 143.28 ;
        END
    END s_w[22]
    PIN s_w[23]
        DIRECTION INPUT ; 
        USE SIGNAL ; 
        PORT
            LAYER met1 ;
              RECT  0 58.58 0.595 58.72 ;
        END
    END s_w[23]
    PIN s_w[24]
        DIRECTION INPUT ; 
        USE SIGNAL ; 
        PORT
            LAYER met2 ;
              RECT  33.28 0 33.42 0.485 ;
        END
    END s_w[24]
    PIN s_w[25]
        DIRECTION INPUT ; 
        USE SIGNAL ; 
        PORT
            LAYER met2 ;
              RECT  11.2 0 11.34 0.485 ;
        END
    END s_w[25]
    PIN s_w[26]
        DIRECTION INPUT ; 
        USE SIGNAL ; 
        PORT
            LAYER met2 ;
              RECT  75.6 142.795 75.74 143.28 ;
        END
    END s_w[26]
    PIN s_w[27]
        DIRECTION INPUT ; 
        USE SIGNAL ; 
        PORT
            LAYER met2 ;
              RECT  37.88 142.795 38.02 143.28 ;
        END
    END s_w[27]
    PIN s_w[28]
        DIRECTION INPUT ; 
        USE SIGNAL ; 
        PORT
            LAYER met2 ;
              RECT  87.56 0 87.7 0.485 ;
        END
    END s_w[28]
    PIN s_w[29]
        DIRECTION INPUT ; 
        USE SIGNAL ; 
        PORT
            LAYER met2 ;
              RECT  103.2 142.795 103.34 143.28 ;
        END
    END s_w[29]
    PIN s_w[2]
        DIRECTION INPUT ; 
        USE SIGNAL ; 
        PORT
            LAYER met1 ;
              RECT  142.685 49.74 143.28 49.88 ;
        END
    END s_w[2]
    PIN s_w[30]
        DIRECTION INPUT ; 
        USE SIGNAL ; 
        PORT
            LAYER met1 ;
              RECT  0 92.58 0.595 92.72 ;
        END
    END s_w[30]
    PIN s_w[31]
        DIRECTION INPUT ; 
        USE SIGNAL ; 
        PORT
            LAYER met1 ;
              RECT  142.685 109.58 143.28 109.72 ;
        END
    END s_w[31]
    PIN s_w[32]
        DIRECTION INPUT ; 
        USE SIGNAL ; 
        PORT
            LAYER met2 ;
              RECT  36.04 0 36.18 0.485 ;
        END
    END s_w[32]
    PIN s_w[33]
        DIRECTION INPUT ; 
        USE SIGNAL ; 
        PORT
            LAYER met2 ;
              RECT  62.72 0 62.86 0.485 ;
        END
    END s_w[33]
    PIN s_w[34]
        DIRECTION INPUT ; 
        USE SIGNAL ; 
        PORT
            LAYER met2 ;
              RECT  97.68 0 97.82 0.485 ;
        END
    END s_w[34]
    PIN s_w[35]
        DIRECTION INPUT ; 
        USE SIGNAL ; 
        PORT
            LAYER met1 ;
              RECT  142.685 107.54 143.28 107.68 ;
        END
    END s_w[35]
    PIN s_w[3]
        DIRECTION INPUT ; 
        USE SIGNAL ; 
        PORT
            LAYER met2 ;
              RECT  100.44 0 100.58 0.485 ;
        END
    END s_w[3]
    PIN s_w[4]
        DIRECTION INPUT ; 
        USE SIGNAL ; 
        PORT
            LAYER met2 ;
              RECT  89.4 142.795 89.54 143.28 ;
        END
    END s_w[4]
    PIN s_w[5]
        DIRECTION INPUT ; 
        USE SIGNAL ; 
        PORT
            LAYER met2 ;
              RECT  86.64 142.795 86.78 143.28 ;
        END
    END s_w[5]
    PIN s_w[6]
        DIRECTION INPUT ; 
        USE SIGNAL ; 
        PORT
            LAYER met1 ;
              RECT  0 118.42 0.595 118.56 ;
        END
    END s_w[6]
    PIN s_w[7]
        DIRECTION INPUT ; 
        USE SIGNAL ; 
        PORT
            LAYER met1 ;
              RECT  0 140.18 0.595 140.32 ;
        END
    END s_w[7]
    PIN s_w[8]
        DIRECTION INPUT ; 
        USE SIGNAL ; 
        PORT
            LAYER met2 ;
              RECT  119.76 0 119.9 0.485 ;
        END
    END s_w[8]
    PIN s_w[9]
        DIRECTION INPUT ; 
        USE SIGNAL ; 
        PORT
            LAYER met1 ;
              RECT  0 30.7 0.595 30.84 ;
        END
    END s_w[9]
    PIN s_wready
        DIRECTION OUTPUT ; 
        USE SIGNAL ; 
        PORT
            LAYER met1 ;
              RECT  0 104.14 0.595 104.28 ;
        END
    END s_wready
    PIN s_wvalid
        DIRECTION INPUT ; 
        USE SIGNAL ; 
        PORT
            LAYER met1 ;
              RECT  142.685 79.66 143.28 79.8 ;
        END
    END s_wvalid
    PIN VGND
        DIRECTION INOUT ; 
        USE GROUND ; 
        PORT
            LAYER met2 ;
              RECT  22.92 10.695 24.46 11.065 ;
        END
        PORT
            LAYER met2 ;
              RECT  50.06 10.695 51.6 11.065 ;
        END
        PORT
            LAYER met2 ;
              RECT  77.2 10.695 78.74 11.065 ;
        END
        PORT
            LAYER met2 ;
              RECT  104.34 10.695 105.88 11.065 ;
        END
        PORT
            LAYER met2 ;
              RECT  131.48 10.695 133.02 11.065 ;
        END
        PORT
            LAYER met2 ;
              RECT  131.48 10.695 133.02 11.065 ;
        END
        PORT
            LAYER met2 ;
              RECT  131.48 16.135 133.02 16.505 ;
        END
        PORT
            LAYER met2 ;
              RECT  131.48 21.575 133.02 21.945 ;
        END
        PORT
            LAYER met2 ;
              RECT  131.48 27.015 133.02 27.385 ;
        END
        PORT
            LAYER met2 ;
              RECT  131.48 32.455 133.02 32.825 ;
        END
        PORT
            LAYER met2 ;
              RECT  131.48 37.895 133.02 38.265 ;
        END
        PORT
            LAYER met2 ;
              RECT  131.48 43.335 133.02 43.705 ;
        END
        PORT
            LAYER met2 ;
              RECT  131.48 48.775 133.02 49.145 ;
        END
        PORT
            LAYER met2 ;
              RECT  131.48 54.215 133.02 54.585 ;
        END
        PORT
            LAYER met2 ;
              RECT  131.48 59.655 133.02 60.025 ;
        END
        PORT
            LAYER met2 ;
              RECT  131.48 65.095 133.02 65.465 ;
        END
        PORT
            LAYER met2 ;
              RECT  131.48 70.535 133.02 70.905 ;
        END
        PORT
            LAYER met2 ;
              RECT  131.48 75.975 133.02 76.345 ;
        END
        PORT
            LAYER met2 ;
              RECT  131.48 81.415 133.02 81.785 ;
        END
        PORT
            LAYER met2 ;
              RECT  131.48 86.855 133.02 87.225 ;
        END
        PORT
            LAYER met2 ;
              RECT  131.48 92.295 133.02 92.665 ;
        END
        PORT
            LAYER met2 ;
              RECT  131.48 97.735 133.02 98.105 ;
        END
        PORT
            LAYER met2 ;
              RECT  131.48 103.175 133.02 103.545 ;
        END
        PORT
            LAYER met2 ;
              RECT  131.48 108.615 133.02 108.985 ;
        END
        PORT
            LAYER met2 ;
              RECT  131.48 114.055 133.02 114.425 ;
        END
        PORT
            LAYER met2 ;
              RECT  131.48 119.495 133.02 119.865 ;
        END
        PORT
            LAYER met2 ;
              RECT  131.48 124.935 133.02 125.305 ;
        END
        PORT
            LAYER met2 ;
              RECT  131.48 130.375 133.02 130.745 ;
        END
        PORT
            LAYER met3 ;
              RECT  22.9 10.715 24.48 11.045 ;
        END
        PORT
            LAYER met3 ;
              RECT  50.04 10.715 51.62 11.045 ;
        END
        PORT
            LAYER met3 ;
              RECT  77.18 10.715 78.76 11.045 ;
        END
        PORT
            LAYER met3 ;
              RECT  104.32 10.715 105.9 11.045 ;
        END
        PORT
            LAYER met3 ;
              RECT  131.46 10.715 133.04 11.045 ;
        END
        PORT
            LAYER met3 ;
              RECT  131.46 10.715 133.04 11.045 ;
        END
        PORT
            LAYER met3 ;
              RECT  131.46 16.155 133.04 16.485 ;
        END
        PORT
            LAYER met3 ;
              RECT  131.46 21.595 133.04 21.925 ;
        END
        PORT
            LAYER met3 ;
              RECT  131.46 27.035 133.04 27.365 ;
        END
        PORT
            LAYER met3 ;
              RECT  131.46 32.475 133.04 32.805 ;
        END
        PORT
            LAYER met3 ;
              RECT  131.46 37.915 133.04 38.245 ;
        END
        PORT
            LAYER met3 ;
              RECT  131.46 43.355 133.04 43.685 ;
        END
        PORT
            LAYER met3 ;
              RECT  131.46 48.795 133.04 49.125 ;
        END
        PORT
            LAYER met3 ;
              RECT  131.46 54.235 133.04 54.565 ;
        END
        PORT
            LAYER met3 ;
              RECT  131.46 59.675 133.04 60.005 ;
        END
        PORT
            LAYER met3 ;
              RECT  131.46 65.115 133.04 65.445 ;
        END
        PORT
            LAYER met3 ;
              RECT  131.46 70.555 133.04 70.885 ;
        END
        PORT
            LAYER met3 ;
              RECT  131.46 75.995 133.04 76.325 ;
        END
        PORT
            LAYER met3 ;
              RECT  131.46 81.435 133.04 81.765 ;
        END
        PORT
            LAYER met3 ;
              RECT  131.46 86.875 133.04 87.205 ;
        END
        PORT
            LAYER met3 ;
              RECT  131.46 92.315 133.04 92.645 ;
        END
        PORT
            LAYER met3 ;
              RECT  131.46 97.755 133.04 98.085 ;
        END
        PORT
            LAYER met3 ;
              RECT  131.46 103.195 133.04 103.525 ;
        END
        PORT
            LAYER met3 ;
              RECT  131.46 108.635 133.04 108.965 ;
        END
        PORT
            LAYER met3 ;
              RECT  131.46 114.075 133.04 114.405 ;
        END
        PORT
            LAYER met3 ;
              RECT  131.46 119.515 133.04 119.845 ;
        END
        PORT
            LAYER met3 ;
              RECT  131.46 124.955 133.04 125.285 ;
        END
        PORT
            LAYER met3 ;
              RECT  131.46 130.395 133.04 130.725 ;
        END
        PORT
            LAYER met1 ;
              RECT  10.12 10.64 133.05 11.12 ;
        END
        PORT
            LAYER met1 ;
              RECT  131.05 10.64 133.05 11.12 ;
        END
        PORT
            LAYER met1 ;
              RECT  10.12 10.64 12.12 11.12 ;
        END
        PORT
            LAYER met1 ;
              RECT  131.05 16.08 133.05 16.56 ;
        END
        PORT
            LAYER met1 ;
              RECT  10.12 16.08 12.12 16.56 ;
        END
        PORT
            LAYER met1 ;
              RECT  131.05 21.52 133.05 22 ;
        END
        PORT
            LAYER met1 ;
              RECT  10.12 21.52 12.12 22 ;
        END
        PORT
            LAYER met1 ;
              RECT  131.05 26.96 133.05 27.44 ;
        END
        PORT
            LAYER met1 ;
              RECT  10.12 26.96 12.12 27.44 ;
        END
        PORT
            LAYER met1 ;
              RECT  131.05 32.4 133.05 32.88 ;
        END
        PORT
            LAYER met1 ;
              RECT  10.12 32.4 12.12 32.88 ;
        END
        PORT
            LAYER met1 ;
              RECT  131.05 37.84 133.05 38.32 ;
        END
        PORT
            LAYER met1 ;
              RECT  10.12 37.84 12.12 38.32 ;
        END
        PORT
            LAYER met1 ;
              RECT  131.05 43.28 133.05 43.76 ;
        END
        PORT
            LAYER met1 ;
              RECT  10.12 43.28 12.12 43.76 ;
        END
        PORT
            LAYER met1 ;
              RECT  131.05 48.72 133.05 49.2 ;
        END
        PORT
            LAYER met1 ;
              RECT  10.12 48.72 12.12 49.2 ;
        END
        PORT
            LAYER met1 ;
              RECT  131.05 54.16 133.05 54.64 ;
        END
        PORT
            LAYER met1 ;
              RECT  10.12 54.16 12.12 54.64 ;
        END
        PORT
            LAYER met1 ;
              RECT  131.05 59.6 133.05 60.08 ;
        END
        PORT
            LAYER met1 ;
              RECT  10.12 59.6 12.12 60.08 ;
        END
        PORT
            LAYER met1 ;
              RECT  131.05 65.04 133.05 65.52 ;
        END
        PORT
            LAYER met1 ;
              RECT  10.12 65.04 12.12 65.52 ;
        END
        PORT
            LAYER met1 ;
              RECT  131.05 70.48 133.05 70.96 ;
        END
        PORT
            LAYER met1 ;
              RECT  10.12 70.48 12.12 70.96 ;
        END
        PORT
            LAYER met1 ;
              RECT  131.05 75.92 133.05 76.4 ;
        END
        PORT
            LAYER met1 ;
              RECT  10.12 75.92 12.12 76.4 ;
        END
        PORT
            LAYER met1 ;
              RECT  131.05 81.36 133.05 81.84 ;
        END
        PORT
            LAYER met1 ;
              RECT  10.12 81.36 12.12 81.84 ;
        END
        PORT
            LAYER met1 ;
              RECT  131.05 86.8 133.05 87.28 ;
        END
        PORT
            LAYER met1 ;
              RECT  10.12 86.8 12.12 87.28 ;
        END
        PORT
            LAYER met1 ;
              RECT  131.05 92.24 133.05 92.72 ;
        END
        PORT
            LAYER met1 ;
              RECT  10.12 92.24 12.12 92.72 ;
        END
        PORT
            LAYER met1 ;
              RECT  131.05 97.68 133.05 98.16 ;
        END
        PORT
            LAYER met1 ;
              RECT  10.12 97.68 12.12 98.16 ;
        END
        PORT
            LAYER met1 ;
              RECT  131.05 103.12 133.05 103.6 ;
        END
        PORT
            LAYER met1 ;
              RECT  10.12 103.12 12.12 103.6 ;
        END
        PORT
            LAYER met1 ;
              RECT  131.05 108.56 133.05 109.04 ;
        END
        PORT
            LAYER met1 ;
              RECT  10.12 108.56 12.12 109.04 ;
        END
        PORT
            LAYER met1 ;
              RECT  131.05 114 133.05 114.48 ;
        END
        PORT
            LAYER met1 ;
              RECT  10.12 114 12.12 114.48 ;
        END
        PORT
            LAYER met1 ;
              RECT  131.05 119.44 133.05 119.92 ;
        END
        PORT
            LAYER met1 ;
              RECT  10.12 119.44 12.12 119.92 ;
        END
        PORT
            LAYER met1 ;
              RECT  131.05 124.88 133.05 125.36 ;
        END
        PORT
            LAYER met1 ;
              RECT  10.12 124.88 12.12 125.36 ;
        END
        PORT
            LAYER met1 ;
              RECT  131.05 130.32 133.05 130.8 ;
        END
        PORT
            LAYER met1 ;
              RECT  10.12 130.32 12.12 130.8 ;
        END
        PORT
            LAYER met4 ;
              RECT  22.89 10.64 24.49 12.64 ;
        END
        PORT
            LAYER met4 ;
              RECT  50.03 10.64 51.63 12.64 ;
        END
        PORT
            LAYER met4 ;
              RECT  77.17 10.64 78.77 12.64 ;
        END
        PORT
            LAYER met4 ;
              RECT  104.31 10.64 105.91 12.64 ;
        END
        PORT
            LAYER met4 ;
              RECT  131.45 10.64 133.05 12.64 ;
        END
        PORT
            LAYER met4 ;
              RECT  131.45 10.64 133.05 130.8 ;
        END
        PORT
            LAYER met5 ;
              RECT  131.05 23.68 133.05 25.28 ;
        END
        PORT
            LAYER met5 ;
              RECT  131.05 50.88 133.05 52.48 ;
        END
        PORT
            LAYER met5 ;
              RECT  131.05 78.08 133.05 79.68 ;
        END
        PORT
            LAYER met5 ;
              RECT  131.05 105.28 133.05 106.88 ;
        END
    END VGND
    PIN VPWR
        DIRECTION INOUT ; 
        USE POWER ; 
        PORT
            LAYER met1 ;
              RECT  130.94 13.36 132.94 13.84 ;
        END
        PORT
            LAYER met1 ;
              RECT  10.12 13.36 12.12 13.84 ;
        END
        PORT
            LAYER met1 ;
              RECT  130.94 18.8 132.94 19.28 ;
        END
        PORT
            LAYER met1 ;
              RECT  10.12 18.8 12.12 19.28 ;
        END
        PORT
            LAYER met1 ;
              RECT  130.94 24.24 132.94 24.72 ;
        END
        PORT
            LAYER met1 ;
              RECT  10.12 24.24 12.12 24.72 ;
        END
        PORT
            LAYER met1 ;
              RECT  130.94 29.68 132.94 30.16 ;
        END
        PORT
            LAYER met1 ;
              RECT  10.12 29.68 12.12 30.16 ;
        END
        PORT
            LAYER met1 ;
              RECT  130.94 35.12 132.94 35.6 ;
        END
        PORT
            LAYER met1 ;
              RECT  10.12 35.12 12.12 35.6 ;
        END
        PORT
            LAYER met1 ;
              RECT  130.94 40.56 132.94 41.04 ;
        END
        PORT
            LAYER met1 ;
              RECT  10.12 40.56 12.12 41.04 ;
        END
        PORT
            LAYER met1 ;
              RECT  130.94 46 132.94 46.48 ;
        END
        PORT
            LAYER met1 ;
              RECT  10.12 46 12.12 46.48 ;
        END
        PORT
            LAYER met1 ;
              RECT  130.94 51.44 132.94 51.92 ;
        END
        PORT
            LAYER met1 ;
              RECT  10.12 51.44 12.12 51.92 ;
        END
        PORT
            LAYER met1 ;
              RECT  130.94 56.88 132.94 57.36 ;
        END
        PORT
            LAYER met1 ;
              RECT  10.12 56.88 12.12 57.36 ;
        END
        PORT
            LAYER met1 ;
              RECT  130.94 62.32 132.94 62.8 ;
        END
        PORT
            LAYER met1 ;
              RECT  10.12 62.32 12.12 62.8 ;
        END
        PORT
            LAYER met1 ;
              RECT  130.94 67.76 132.94 68.24 ;
        END
        PORT
            LAYER met1 ;
              RECT  10.12 67.76 12.12 68.24 ;
        END
        PORT
            LAYER met1 ;
              RECT  130.94 73.2 132.94 73.68 ;
        END
        PORT
            LAYER met1 ;
              RECT  10.12 73.2 12.12 73.68 ;
        END
        PORT
            LAYER met1 ;
              RECT  130.94 78.64 132.94 79.12 ;
        END
        PORT
            LAYER met1 ;
              RECT  10.12 78.64 12.12 79.12 ;
        END
        PORT
            LAYER met1 ;
              RECT  130.94 84.08 132.94 84.56 ;
        END
        PORT
            LAYER met1 ;
              RECT  10.12 84.08 12.12 84.56 ;
        END
        PORT
            LAYER met1 ;
              RECT  130.94 89.52 132.94 90 ;
        END
        PORT
            LAYER met1 ;
              RECT  10.12 89.52 12.12 90 ;
        END
        PORT
            LAYER met1 ;
              RECT  130.94 94.96 132.94 95.44 ;
        END
        PORT
            LAYER met1 ;
              RECT  10.12 94.96 12.12 95.44 ;
        END
        PORT
            LAYER met1 ;
              RECT  130.94 100.4 132.94 100.88 ;
        END
        PORT
            LAYER met1 ;
              RECT  10.12 100.4 12.12 100.88 ;
        END
        PORT
            LAYER met1 ;
              RECT  130.94 105.84 132.94 106.32 ;
        END
        PORT
            LAYER met1 ;
              RECT  10.12 105.84 12.12 106.32 ;
        END
        PORT
            LAYER met1 ;
              RECT  130.94 111.28 132.94 111.76 ;
        END
        PORT
            LAYER met1 ;
              RECT  10.12 111.28 12.12 111.76 ;
        END
        PORT
            LAYER met1 ;
              RECT  130.94 116.72 132.94 117.2 ;
        END
        PORT
            LAYER met1 ;
              RECT  10.12 116.72 12.12 117.2 ;
        END
        PORT
            LAYER met1 ;
              RECT  130.94 122.16 132.94 122.64 ;
        END
        PORT
            LAYER met1 ;
              RECT  10.12 122.16 12.12 122.64 ;
        END
        PORT
            LAYER met1 ;
              RECT  130.94 127.6 132.94 128.08 ;
        END
        PORT
            LAYER met1 ;
              RECT  10.12 127.6 12.12 128.08 ;
        END
    END VPWR
    OBS
      LAYER met5 ;
        RECT  0 106.88 143.28 143.28 ;
        RECT  133.05 105.28 143.28 106.88 ;
        RECT  0 105.28 131.05 106.88 ;
        RECT  0 79.68 143.28 105.28 ;
        RECT  133.05 78.08 143.28 79.68 ;
        RECT  0 78.08 131.05 79.68 ;
        RECT  0 52.48 143.28 78.08 ;
        RECT  133.05 50.88 143.28 52.48 ;
        RECT  0 50.88 131.05 52.48 ;
        RECT  0 25.28 143.28 50.88 ;
        RECT  133.05 23.68 143.28 25.28 ;
        RECT  0 23.68 131.05 25.28 ;
        RECT  0 0 143.28 23.68 ;
      LAYER met4 ;
        RECT  0 130.8 143.28 143.28 ;
        RECT  133.05 12.64 143.28 130.8 ;
        RECT  0 12.64 131.45 130.8 ;
        RECT  133.05 10.64 143.28 12.64 ;
        RECT  105.91 10.64 131.45 12.64 ;
        RECT  78.77 10.64 104.31 12.64 ;
        RECT  51.63 10.64 77.17 12.64 ;
        RECT  24.49 10.64 50.03 12.64 ;
        RECT  0 10.64 22.89 12.64 ;
        RECT  0 0 143.28 10.64 ;
      LAYER met3 ;
        RECT  0 130.725 143.28 143.28 ;
        RECT  133.04 130.395 143.28 130.725 ;
        RECT  0 130.395 131.46 130.725 ;
        RECT  0 125.285 143.28 130.395 ;
        RECT  133.04 124.955 143.28 125.285 ;
        RECT  0 124.955 131.46 125.285 ;
        RECT  0 119.845 143.28 124.955 ;
        RECT  133.04 119.515 143.28 119.845 ;
        RECT  0 119.515 131.46 119.845 ;
        RECT  0 114.405 143.28 119.515 ;
        RECT  133.04 114.075 143.28 114.405 ;
        RECT  0 114.075 131.46 114.405 ;
        RECT  0 108.965 143.28 114.075 ;
        RECT  133.04 108.635 143.28 108.965 ;
        RECT  0 108.635 131.46 108.965 ;
        RECT  0 103.525 143.28 108.635 ;
        RECT  133.04 103.195 143.28 103.525 ;
        RECT  0 103.195 131.46 103.525 ;
        RECT  0 98.085 143.28 103.195 ;
        RECT  133.04 97.755 143.28 98.085 ;
        RECT  0 97.755 131.46 98.085 ;
        RECT  0 92.645 143.28 97.755 ;
        RECT  133.04 92.315 143.28 92.645 ;
        RECT  0 92.315 131.46 92.645 ;
        RECT  0 87.205 143.28 92.315 ;
        RECT  133.04 86.875 143.28 87.205 ;
        RECT  0 86.875 131.46 87.205 ;
        RECT  0 81.765 143.28 86.875 ;
        RECT  133.04 81.435 143.28 81.765 ;
        RECT  0 81.435 131.46 81.765 ;
        RECT  0 76.325 143.28 81.435 ;
        RECT  133.04 75.995 143.28 76.325 ;
        RECT  0 75.995 131.46 76.325 ;
        RECT  0 70.885 143.28 75.995 ;
        RECT  133.04 70.555 143.28 70.885 ;
        RECT  0 70.555 131.46 70.885 ;
        RECT  0 65.445 143.28 70.555 ;
        RECT  133.04 65.115 143.28 65.445 ;
        RECT  0 65.115 131.46 65.445 ;
        RECT  0 60.005 143.28 65.115 ;
        RECT  133.04 59.675 143.28 60.005 ;
        RECT  0 59.675 131.46 60.005 ;
        RECT  0 54.565 143.28 59.675 ;
        RECT  133.04 54.235 143.28 54.565 ;
        RECT  0 54.235 131.46 54.565 ;
        RECT  0 49.125 143.28 54.235 ;
        RECT  133.04 48.795 143.28 49.125 ;
        RECT  0 48.795 131.46 49.125 ;
        RECT  0 43.685 143.28 48.795 ;
        RECT  133.04 43.355 143.28 43.685 ;
        RECT  0 43.355 131.46 43.685 ;
        RECT  0 38.245 143.28 43.355 ;
        RECT  133.04 37.915 143.28 38.245 ;
        RECT  0 37.915 131.46 38.245 ;
        RECT  0 32.805 143.28 37.915 ;
        RECT  133.04 32.475 143.28 32.805 ;
        RECT  0 32.475 131.46 32.805 ;
        RECT  0 27.365 143.28 32.475 ;
        RECT  133.04 27.035 143.28 27.365 ;
        RECT  0 27.035 131.46 27.365 ;
        RECT  0 21.925 143.28 27.035 ;
        RECT  133.04 21.595 143.28 21.925 ;
        RECT  0 21.595 131.46 21.925 ;
        RECT  0 16.485 143.28 21.595 ;
        RECT  133.04 16.155 143.28 16.485 ;
        RECT  0 16.155 131.46 16.485 ;
        RECT  0 11.045 143.28 16.155 ;
        RECT  133.04 10.715 143.28 11.045 ;
        RECT  105.9 10.715 131.46 11.045 ;
        RECT  78.76 10.715 104.32 11.045 ;
        RECT  51.62 10.715 77.18 11.045 ;
        RECT  24.48 10.715 50.04 11.045 ;
        RECT  0 10.715 22.9 11.045 ;
        RECT  0 0 143.28 10.715 ;
      LAYER met2 ;
        RECT  141.06 142.795 143.28 143.28 ;
        RECT  138.3 142.795 140.92 143.28 ;
        RECT  135.54 142.795 138.16 143.28 ;
        RECT  132.78 142.795 135.4 143.28 ;
        RECT  130.02 142.795 132.64 143.28 ;
        RECT  127.26 142.795 129.88 143.28 ;
        RECT  124.5 142.795 127.12 143.28 ;
        RECT  121.74 142.795 124.36 143.28 ;
        RECT  119.9 142.795 121.6 143.28 ;
        RECT  117.14 142.795 119.76 143.28 ;
        RECT  114.38 142.795 117 143.28 ;
        RECT  111.62 142.795 114.24 143.28 ;
        RECT  108.86 142.795 111.48 143.28 ;
        RECT  106.1 142.795 108.72 143.28 ;
        RECT  103.34 142.795 105.96 143.28 ;
        RECT  100.58 142.795 103.2 143.28 ;
        RECT  97.82 142.795 100.44 143.28 ;
        RECT  95.06 142.795 97.68 143.28 ;
        RECT  92.3 142.795 94.92 143.28 ;
        RECT  89.54 142.795 92.16 143.28 ;
        RECT  86.78 142.795 89.4 143.28 ;
        RECT  84.02 142.795 86.64 143.28 ;
        RECT  81.26 142.795 83.88 143.28 ;
        RECT  78.5 142.795 81.12 143.28 ;
        RECT  75.74 142.795 78.36 143.28 ;
        RECT  73.9 142.795 75.6 143.28 ;
        RECT  71.14 142.795 73.76 143.28 ;
        RECT  68.38 142.795 71 143.28 ;
        RECT  65.62 142.795 68.24 143.28 ;
        RECT  62.86 142.795 65.48 143.28 ;
        RECT  60.1 142.795 62.72 143.28 ;
        RECT  57.34 142.795 59.96 143.28 ;
        RECT  54.58 142.795 57.2 143.28 ;
        RECT  51.82 142.795 54.44 143.28 ;
        RECT  49.06 142.795 51.68 143.28 ;
        RECT  46.3 142.795 48.92 143.28 ;
        RECT  43.54 142.795 46.16 143.28 ;
        RECT  40.78 142.795 43.4 143.28 ;
        RECT  38.02 142.795 40.64 143.28 ;
        RECT  35.26 142.795 37.88 143.28 ;
        RECT  32.5 142.795 35.12 143.28 ;
        RECT  30.66 142.795 32.36 143.28 ;
        RECT  27.9 142.795 30.52 143.28 ;
        RECT  25.14 142.795 27.76 143.28 ;
        RECT  22.38 142.795 25 143.28 ;
        RECT  19.62 142.795 22.24 143.28 ;
        RECT  16.86 142.795 19.48 143.28 ;
        RECT  14.1 142.795 16.72 143.28 ;
        RECT  11.34 142.795 13.96 143.28 ;
        RECT  8.58 142.795 11.2 143.28 ;
        RECT  5.82 142.795 8.44 143.28 ;
        RECT  3.06 142.795 5.68 143.28 ;
        RECT  0 142.795 2.92 143.28 ;
        RECT  0 130.745 143.28 142.795 ;
        RECT  133.02 130.375 143.28 130.745 ;
        RECT  0 130.375 131.48 130.745 ;
        RECT  0 125.305 143.28 130.375 ;
        RECT  133.02 124.935 143.28 125.305 ;
        RECT  0 124.935 131.48 125.305 ;
        RECT  0 119.865 143.28 124.935 ;
        RECT  133.02 119.495 143.28 119.865 ;
        RECT  0 119.495 131.48 119.865 ;
        RECT  0 114.425 143.28 119.495 ;
        RECT  133.02 114.055 143.28 114.425 ;
        RECT  0 114.055 131.48 114.425 ;
        RECT  0 108.985 143.28 114.055 ;
        RECT  133.02 108.615 143.28 108.985 ;
        RECT  0 108.615 131.48 108.985 ;
        RECT  0 103.545 143.28 108.615 ;
        RECT  133.02 103.175 143.28 103.545 ;
        RECT  0 103.175 131.48 103.545 ;
        RECT  0 98.105 143.28 103.175 ;
        RECT  133.02 97.735 143.28 98.105 ;
        RECT  0 97.735 131.48 98.105 ;
        RECT  0 92.665 143.28 97.735 ;
        RECT  133.02 92.295 143.28 92.665 ;
        RECT  0 92.295 131.48 92.665 ;
        RECT  0 87.225 143.28 92.295 ;
        RECT  133.02 86.855 143.28 87.225 ;
        RECT  0 86.855 131.48 87.225 ;
        RECT  0 81.785 143.28 86.855 ;
        RECT  133.02 81.415 143.28 81.785 ;
        RECT  0 81.415 131.48 81.785 ;
        RECT  0 76.345 143.28 81.415 ;
        RECT  133.02 75.975 143.28 76.345 ;
        RECT  0 75.975 131.48 76.345 ;
        RECT  0 70.905 143.28 75.975 ;
        RECT  133.02 70.535 143.28 70.905 ;
        RECT  0 70.535 131.48 70.905 ;
        RECT  0 65.465 143.28 70.535 ;
        RECT  133.02 65.095 143.28 65.465 ;
        RECT  0 65.095 131.48 65.465 ;
        RECT  0 60.025 143.28 65.095 ;
        RECT  133.02 59.655 143.28 60.025 ;
        RECT  0 59.655 131.48 60.025 ;
        RECT  0 54.585 143.28 59.655 ;
        RECT  133.02 54.215 143.28 54.585 ;
        RECT  0 54.215 131.48 54.585 ;
        RECT  0 49.145 143.28 54.215 ;
        RECT  133.02 48.775 143.28 49.145 ;
        RECT  0 48.775 131.48 49.145 ;
        RECT  0 43.705 143.28 48.775 ;
        RECT  133.02 43.335 143.28 43.705 ;
        RECT  0 43.335 131.48 43.705 ;
        RECT  0 38.265 143.28 43.335 ;
        RECT  133.02 37.895 143.28 38.265 ;
        RECT  0 37.895 131.48 38.265 ;
        RECT  0 32.825 143.28 37.895 ;
        RECT  133.02 32.455 143.28 32.825 ;
        RECT  0 32.455 131.48 32.825 ;
        RECT  0 27.385 143.28 32.455 ;
        RECT  133.02 27.015 143.28 27.385 ;
        RECT  0 27.015 131.48 27.385 ;
        RECT  0 21.945 143.28 27.015 ;
        RECT  133.02 21.575 143.28 21.945 ;
        RECT  0 21.575 131.48 21.945 ;
        RECT  0 16.505 143.28 21.575 ;
        RECT  133.02 16.135 143.28 16.505 ;
        RECT  0 16.135 131.48 16.505 ;
        RECT  0 11.065 143.28 16.135 ;
        RECT  133.02 10.695 143.28 11.065 ;
        RECT  105.88 10.695 131.48 11.065 ;
        RECT  78.74 10.695 104.34 11.065 ;
        RECT  51.6 10.695 77.2 11.065 ;
        RECT  24.46 10.695 50.06 11.065 ;
        RECT  0 10.695 22.92 11.065 ;
        RECT  0 0.485 143.28 10.695 ;
        RECT  141.06 0 143.28 0.485 ;
        RECT  138.3 0 140.92 0.485 ;
        RECT  135.54 0 138.16 0.485 ;
        RECT  133.7 0 135.4 0.485 ;
        RECT  130.94 0 133.56 0.485 ;
        RECT  128.18 0 130.8 0.485 ;
        RECT  125.42 0 128.04 0.485 ;
        RECT  122.66 0 125.28 0.485 ;
        RECT  119.9 0 122.52 0.485 ;
        RECT  117.14 0 119.76 0.485 ;
        RECT  114.38 0 117 0.485 ;
        RECT  111.62 0 114.24 0.485 ;
        RECT  108.86 0 111.48 0.485 ;
        RECT  106.1 0 108.72 0.485 ;
        RECT  103.34 0 105.96 0.485 ;
        RECT  100.58 0 103.2 0.485 ;
        RECT  97.82 0 100.44 0.485 ;
        RECT  95.06 0 97.68 0.485 ;
        RECT  92.3 0 94.92 0.485 ;
        RECT  89.54 0 92.16 0.485 ;
        RECT  87.7 0 89.4 0.485 ;
        RECT  84.94 0 87.56 0.485 ;
        RECT  82.18 0 84.8 0.485 ;
        RECT  79.42 0 82.04 0.485 ;
        RECT  76.66 0 79.28 0.485 ;
        RECT  73.9 0 76.52 0.485 ;
        RECT  71.14 0 73.76 0.485 ;
        RECT  68.38 0 71 0.485 ;
        RECT  65.62 0 68.24 0.485 ;
        RECT  62.86 0 65.48 0.485 ;
        RECT  60.1 0 62.72 0.485 ;
        RECT  57.34 0 59.96 0.485 ;
        RECT  54.58 0 57.2 0.485 ;
        RECT  51.82 0 54.44 0.485 ;
        RECT  49.06 0 51.68 0.485 ;
        RECT  46.3 0 48.92 0.485 ;
        RECT  44.46 0 46.16 0.485 ;
        RECT  41.7 0 44.32 0.485 ;
        RECT  38.94 0 41.56 0.485 ;
        RECT  36.18 0 38.8 0.485 ;
        RECT  33.42 0 36.04 0.485 ;
        RECT  30.66 0 33.28 0.485 ;
        RECT  27.9 0 30.52 0.485 ;
        RECT  25.14 0 27.76 0.485 ;
        RECT  22.38 0 25 0.485 ;
        RECT  19.62 0 22.24 0.485 ;
        RECT  16.86 0 19.48 0.485 ;
        RECT  14.1 0 16.72 0.485 ;
        RECT  11.34 0 13.96 0.485 ;
        RECT  8.58 0 11.2 0.485 ;
        RECT  5.82 0 8.44 0.485 ;
        RECT  3.06 0 5.68 0.485 ;
        RECT  1.22 0 2.92 0.485 ;
        RECT  0 0 1.08 0.485 ;
      LAYER met1 ;
        RECT  0 142.36 143.28 143.28 ;
        RECT  0.595 142.22 143.28 142.36 ;
        RECT  0 141.68 143.28 142.22 ;
        RECT  0 141.54 142.685 141.68 ;
        RECT  0 140.32 143.28 141.54 ;
        RECT  0.595 140.18 143.28 140.32 ;
        RECT  0 139.64 143.28 140.18 ;
        RECT  0 139.5 142.685 139.64 ;
        RECT  0 138.28 143.28 139.5 ;
        RECT  0.595 138.14 143.28 138.28 ;
        RECT  0 137.6 143.28 138.14 ;
        RECT  0 137.46 142.685 137.6 ;
        RECT  0 136.24 143.28 137.46 ;
        RECT  0.595 136.1 143.28 136.24 ;
        RECT  0 135.56 143.28 136.1 ;
        RECT  0 135.42 142.685 135.56 ;
        RECT  0 134.2 143.28 135.42 ;
        RECT  0.595 134.06 143.28 134.2 ;
        RECT  0 133.52 143.28 134.06 ;
        RECT  0 133.38 142.685 133.52 ;
        RECT  0 132.16 143.28 133.38 ;
        RECT  0.595 132.02 143.28 132.16 ;
        RECT  0 131.48 143.28 132.02 ;
        RECT  0 131.34 142.685 131.48 ;
        RECT  0 130.8 143.28 131.34 ;
        RECT  133.05 130.66 143.28 130.8 ;
        RECT  12.12 130.66 131.05 130.8 ;
        RECT  0.595 130.66 10.12 130.8 ;
        RECT  133.05 130.32 143.28 130.66 ;
        RECT  12.12 130.32 131.05 130.66 ;
        RECT  0 130.32 10.12 130.66 ;
        RECT  0 129.44 143.28 130.32 ;
        RECT  0 129.3 142.685 129.44 ;
        RECT  0 128.76 143.28 129.3 ;
        RECT  0.595 128.62 143.28 128.76 ;
        RECT  0 128.08 143.28 128.62 ;
        RECT  132.94 127.6 143.28 128.08 ;
        RECT  12.12 127.6 130.94 128.08 ;
        RECT  0 127.6 10.12 128.08 ;
        RECT  0 127.4 143.28 127.6 ;
        RECT  0 127.26 142.685 127.4 ;
        RECT  0 126.72 143.28 127.26 ;
        RECT  0.595 126.58 143.28 126.72 ;
        RECT  0 126.04 143.28 126.58 ;
        RECT  0 125.9 142.685 126.04 ;
        RECT  0 125.36 143.28 125.9 ;
        RECT  133.05 124.88 143.28 125.36 ;
        RECT  12.12 124.88 131.05 125.36 ;
        RECT  0 124.88 10.12 125.36 ;
        RECT  0 124.68 143.28 124.88 ;
        RECT  0.595 124.54 143.28 124.68 ;
        RECT  0 124 143.28 124.54 ;
        RECT  0 123.86 142.685 124 ;
        RECT  0 122.64 143.28 123.86 ;
        RECT  132.94 122.5 143.28 122.64 ;
        RECT  12.12 122.5 130.94 122.64 ;
        RECT  0.595 122.5 10.12 122.64 ;
        RECT  132.94 122.16 143.28 122.5 ;
        RECT  12.12 122.16 130.94 122.5 ;
        RECT  0 122.16 10.12 122.5 ;
        RECT  0 121.96 143.28 122.16 ;
        RECT  0 121.82 142.685 121.96 ;
        RECT  0 120.6 143.28 121.82 ;
        RECT  0.595 120.46 143.28 120.6 ;
        RECT  0 119.92 143.28 120.46 ;
        RECT  133.05 119.78 142.685 119.92 ;
        RECT  12.12 119.78 131.05 119.92 ;
        RECT  0 119.78 10.12 119.92 ;
        RECT  133.05 119.44 143.28 119.78 ;
        RECT  12.12 119.44 131.05 119.78 ;
        RECT  0 119.44 10.12 119.78 ;
        RECT  0 118.56 143.28 119.44 ;
        RECT  0.595 118.42 143.28 118.56 ;
        RECT  0 117.88 143.28 118.42 ;
        RECT  0 117.74 142.685 117.88 ;
        RECT  0 117.2 143.28 117.74 ;
        RECT  132.94 116.72 143.28 117.2 ;
        RECT  12.12 116.72 130.94 117.2 ;
        RECT  0 116.72 10.12 117.2 ;
        RECT  0 116.52 143.28 116.72 ;
        RECT  0.595 116.38 143.28 116.52 ;
        RECT  0 115.84 143.28 116.38 ;
        RECT  0 115.7 142.685 115.84 ;
        RECT  0 114.48 143.28 115.7 ;
        RECT  133.05 114.34 143.28 114.48 ;
        RECT  12.12 114.34 131.05 114.48 ;
        RECT  0.595 114.34 10.12 114.48 ;
        RECT  133.05 114 143.28 114.34 ;
        RECT  12.12 114 131.05 114.34 ;
        RECT  0 114 10.12 114.34 ;
        RECT  0 113.8 143.28 114 ;
        RECT  0 113.66 142.685 113.8 ;
        RECT  0 112.44 143.28 113.66 ;
        RECT  0.595 112.3 143.28 112.44 ;
        RECT  0 111.76 143.28 112.3 ;
        RECT  132.94 111.62 142.685 111.76 ;
        RECT  12.12 111.62 130.94 111.76 ;
        RECT  0 111.62 10.12 111.76 ;
        RECT  132.94 111.28 143.28 111.62 ;
        RECT  12.12 111.28 130.94 111.62 ;
        RECT  0 111.28 10.12 111.62 ;
        RECT  0 110.4 143.28 111.28 ;
        RECT  0.595 110.26 143.28 110.4 ;
        RECT  0 109.72 143.28 110.26 ;
        RECT  0 109.58 142.685 109.72 ;
        RECT  0 109.04 143.28 109.58 ;
        RECT  133.05 108.56 143.28 109.04 ;
        RECT  12.12 108.56 131.05 109.04 ;
        RECT  0 108.56 10.12 109.04 ;
        RECT  0 108.36 143.28 108.56 ;
        RECT  0.595 108.22 143.28 108.36 ;
        RECT  0 107.68 143.28 108.22 ;
        RECT  0 107.54 142.685 107.68 ;
        RECT  0 106.32 143.28 107.54 ;
        RECT  132.94 106.18 143.28 106.32 ;
        RECT  12.12 106.18 130.94 106.32 ;
        RECT  0.595 106.18 10.12 106.32 ;
        RECT  132.94 105.84 143.28 106.18 ;
        RECT  12.12 105.84 130.94 106.18 ;
        RECT  0 105.84 10.12 106.18 ;
        RECT  0 105.64 143.28 105.84 ;
        RECT  0 105.5 142.685 105.64 ;
        RECT  0 104.28 143.28 105.5 ;
        RECT  0.595 104.14 143.28 104.28 ;
        RECT  0 103.6 143.28 104.14 ;
        RECT  133.05 103.46 142.685 103.6 ;
        RECT  12.12 103.46 131.05 103.6 ;
        RECT  0 103.46 10.12 103.6 ;
        RECT  133.05 103.12 143.28 103.46 ;
        RECT  12.12 103.12 131.05 103.46 ;
        RECT  0 103.12 10.12 103.46 ;
        RECT  0 102.24 143.28 103.12 ;
        RECT  0.595 102.1 143.28 102.24 ;
        RECT  0 101.56 143.28 102.1 ;
        RECT  0 101.42 142.685 101.56 ;
        RECT  0 100.88 143.28 101.42 ;
        RECT  132.94 100.4 143.28 100.88 ;
        RECT  12.12 100.4 130.94 100.88 ;
        RECT  0 100.4 10.12 100.88 ;
        RECT  0 100.2 143.28 100.4 ;
        RECT  0.595 100.06 143.28 100.2 ;
        RECT  0 99.52 143.28 100.06 ;
        RECT  0 99.38 142.685 99.52 ;
        RECT  0 98.84 143.28 99.38 ;
        RECT  0.595 98.7 143.28 98.84 ;
        RECT  0 98.16 143.28 98.7 ;
        RECT  133.05 97.68 143.28 98.16 ;
        RECT  12.12 97.68 131.05 98.16 ;
        RECT  0 97.68 10.12 98.16 ;
        RECT  0 97.48 143.28 97.68 ;
        RECT  0 97.34 142.685 97.48 ;
        RECT  0 96.8 143.28 97.34 ;
        RECT  0.595 96.66 143.28 96.8 ;
        RECT  0 95.44 143.28 96.66 ;
        RECT  132.94 95.3 142.685 95.44 ;
        RECT  12.12 95.3 130.94 95.44 ;
        RECT  0 95.3 10.12 95.44 ;
        RECT  132.94 94.96 143.28 95.3 ;
        RECT  12.12 94.96 130.94 95.3 ;
        RECT  0 94.96 10.12 95.3 ;
        RECT  0 94.76 143.28 94.96 ;
        RECT  0.595 94.62 143.28 94.76 ;
        RECT  0 93.4 143.28 94.62 ;
        RECT  0 93.26 142.685 93.4 ;
        RECT  0 92.72 143.28 93.26 ;
        RECT  133.05 92.58 143.28 92.72 ;
        RECT  12.12 92.58 131.05 92.72 ;
        RECT  0.595 92.58 10.12 92.72 ;
        RECT  133.05 92.24 143.28 92.58 ;
        RECT  12.12 92.24 131.05 92.58 ;
        RECT  0 92.24 10.12 92.58 ;
        RECT  0 92.04 143.28 92.24 ;
        RECT  0 91.9 142.685 92.04 ;
        RECT  0 90.68 143.28 91.9 ;
        RECT  0.595 90.54 143.28 90.68 ;
        RECT  0 90 143.28 90.54 ;
        RECT  132.94 89.86 142.685 90 ;
        RECT  12.12 89.86 130.94 90 ;
        RECT  0 89.86 10.12 90 ;
        RECT  132.94 89.52 143.28 89.86 ;
        RECT  12.12 89.52 130.94 89.86 ;
        RECT  0 89.52 10.12 89.86 ;
        RECT  0 88.64 143.28 89.52 ;
        RECT  0.595 88.5 143.28 88.64 ;
        RECT  0 87.96 143.28 88.5 ;
        RECT  0 87.82 142.685 87.96 ;
        RECT  0 87.28 143.28 87.82 ;
        RECT  133.05 86.8 143.28 87.28 ;
        RECT  12.12 86.8 131.05 87.28 ;
        RECT  0 86.8 10.12 87.28 ;
        RECT  0 86.6 143.28 86.8 ;
        RECT  0.595 86.46 143.28 86.6 ;
        RECT  0 85.92 143.28 86.46 ;
        RECT  0 85.78 142.685 85.92 ;
        RECT  0 84.56 143.28 85.78 ;
        RECT  132.94 84.42 143.28 84.56 ;
        RECT  12.12 84.42 130.94 84.56 ;
        RECT  0.595 84.42 10.12 84.56 ;
        RECT  132.94 84.08 143.28 84.42 ;
        RECT  12.12 84.08 130.94 84.42 ;
        RECT  0 84.08 10.12 84.42 ;
        RECT  0 83.88 143.28 84.08 ;
        RECT  0 83.74 142.685 83.88 ;
        RECT  0 82.52 143.28 83.74 ;
        RECT  0.595 82.38 143.28 82.52 ;
        RECT  0 81.84 143.28 82.38 ;
        RECT  133.05 81.7 142.685 81.84 ;
        RECT  12.12 81.7 131.05 81.84 ;
        RECT  0 81.7 10.12 81.84 ;
        RECT  133.05 81.36 143.28 81.7 ;
        RECT  12.12 81.36 131.05 81.7 ;
        RECT  0 81.36 10.12 81.7 ;
        RECT  0 80.48 143.28 81.36 ;
        RECT  0.595 80.34 143.28 80.48 ;
        RECT  0 79.8 143.28 80.34 ;
        RECT  0 79.66 142.685 79.8 ;
        RECT  0 79.12 143.28 79.66 ;
        RECT  132.94 78.64 143.28 79.12 ;
        RECT  12.12 78.64 130.94 79.12 ;
        RECT  0 78.64 10.12 79.12 ;
        RECT  0 78.44 143.28 78.64 ;
        RECT  0.595 78.3 143.28 78.44 ;
        RECT  0 77.76 143.28 78.3 ;
        RECT  0 77.62 142.685 77.76 ;
        RECT  0 76.4 143.28 77.62 ;
        RECT  133.05 76.26 143.28 76.4 ;
        RECT  12.12 76.26 131.05 76.4 ;
        RECT  0.595 76.26 10.12 76.4 ;
        RECT  133.05 75.92 143.28 76.26 ;
        RECT  12.12 75.92 131.05 76.26 ;
        RECT  0 75.92 10.12 76.26 ;
        RECT  0 75.72 143.28 75.92 ;
        RECT  0 75.58 142.685 75.72 ;
        RECT  0 74.36 143.28 75.58 ;
        RECT  0.595 74.22 143.28 74.36 ;
        RECT  0 73.68 143.28 74.22 ;
        RECT  132.94 73.54 142.685 73.68 ;
        RECT  12.12 73.54 130.94 73.68 ;
        RECT  0 73.54 10.12 73.68 ;
        RECT  132.94 73.2 143.28 73.54 ;
        RECT  12.12 73.2 130.94 73.54 ;
        RECT  0 73.2 10.12 73.54 ;
        RECT  0 72.32 143.28 73.2 ;
        RECT  0.595 72.18 143.28 72.32 ;
        RECT  0 71.64 143.28 72.18 ;
        RECT  0 71.5 142.685 71.64 ;
        RECT  0 70.96 143.28 71.5 ;
        RECT  133.05 70.48 143.28 70.96 ;
        RECT  12.12 70.48 131.05 70.96 ;
        RECT  0 70.48 10.12 70.96 ;
        RECT  0 70.28 143.28 70.48 ;
        RECT  0.595 70.14 143.28 70.28 ;
        RECT  0 69.6 143.28 70.14 ;
        RECT  0 69.46 142.685 69.6 ;
        RECT  0 68.24 143.28 69.46 ;
        RECT  132.94 68.1 143.28 68.24 ;
        RECT  12.12 68.1 130.94 68.24 ;
        RECT  0.595 68.1 10.12 68.24 ;
        RECT  132.94 67.76 143.28 68.1 ;
        RECT  12.12 67.76 130.94 68.1 ;
        RECT  0 67.76 10.12 68.1 ;
        RECT  0 67.56 143.28 67.76 ;
        RECT  0 67.42 142.685 67.56 ;
        RECT  0 66.2 143.28 67.42 ;
        RECT  0.595 66.06 143.28 66.2 ;
        RECT  0 65.52 143.28 66.06 ;
        RECT  133.05 65.38 142.685 65.52 ;
        RECT  12.12 65.38 131.05 65.52 ;
        RECT  0 65.38 10.12 65.52 ;
        RECT  133.05 65.04 143.28 65.38 ;
        RECT  12.12 65.04 131.05 65.38 ;
        RECT  0 65.04 10.12 65.38 ;
        RECT  0 64.84 143.28 65.04 ;
        RECT  0.595 64.7 143.28 64.84 ;
        RECT  0 63.48 143.28 64.7 ;
        RECT  0 63.34 142.685 63.48 ;
        RECT  0 62.8 143.28 63.34 ;
        RECT  132.94 62.66 143.28 62.8 ;
        RECT  12.12 62.66 130.94 62.8 ;
        RECT  0.595 62.66 10.12 62.8 ;
        RECT  132.94 62.32 143.28 62.66 ;
        RECT  12.12 62.32 130.94 62.66 ;
        RECT  0 62.32 10.12 62.66 ;
        RECT  0 61.44 143.28 62.32 ;
        RECT  0 61.3 142.685 61.44 ;
        RECT  0 60.76 143.28 61.3 ;
        RECT  0.595 60.62 143.28 60.76 ;
        RECT  0 60.08 143.28 60.62 ;
        RECT  133.05 59.94 142.685 60.08 ;
        RECT  12.12 59.94 131.05 60.08 ;
        RECT  0 59.94 10.12 60.08 ;
        RECT  133.05 59.6 143.28 59.94 ;
        RECT  12.12 59.6 131.05 59.94 ;
        RECT  0 59.6 10.12 59.94 ;
        RECT  0 58.72 143.28 59.6 ;
        RECT  0.595 58.58 143.28 58.72 ;
        RECT  0 58.04 143.28 58.58 ;
        RECT  0 57.9 142.685 58.04 ;
        RECT  0 57.36 143.28 57.9 ;
        RECT  132.94 56.88 143.28 57.36 ;
        RECT  12.12 56.88 130.94 57.36 ;
        RECT  0 56.88 10.12 57.36 ;
        RECT  0 56.68 143.28 56.88 ;
        RECT  0.595 56.54 143.28 56.68 ;
        RECT  0 56 143.28 56.54 ;
        RECT  0 55.86 142.685 56 ;
        RECT  0 54.64 143.28 55.86 ;
        RECT  133.05 54.5 143.28 54.64 ;
        RECT  12.12 54.5 131.05 54.64 ;
        RECT  0.595 54.5 10.12 54.64 ;
        RECT  133.05 54.16 143.28 54.5 ;
        RECT  12.12 54.16 131.05 54.5 ;
        RECT  0 54.16 10.12 54.5 ;
        RECT  0 53.96 143.28 54.16 ;
        RECT  0 53.82 142.685 53.96 ;
        RECT  0 52.6 143.28 53.82 ;
        RECT  0.595 52.46 143.28 52.6 ;
        RECT  0 51.92 143.28 52.46 ;
        RECT  132.94 51.78 142.685 51.92 ;
        RECT  12.12 51.78 130.94 51.92 ;
        RECT  0 51.78 10.12 51.92 ;
        RECT  132.94 51.44 143.28 51.78 ;
        RECT  12.12 51.44 130.94 51.78 ;
        RECT  0 51.44 10.12 51.78 ;
        RECT  0 50.56 143.28 51.44 ;
        RECT  0.595 50.42 143.28 50.56 ;
        RECT  0 49.88 143.28 50.42 ;
        RECT  0 49.74 142.685 49.88 ;
        RECT  0 49.2 143.28 49.74 ;
        RECT  133.05 48.72 143.28 49.2 ;
        RECT  12.12 48.72 131.05 49.2 ;
        RECT  0 48.72 10.12 49.2 ;
        RECT  0 48.52 143.28 48.72 ;
        RECT  0.595 48.38 143.28 48.52 ;
        RECT  0 47.84 143.28 48.38 ;
        RECT  0 47.7 142.685 47.84 ;
        RECT  0 46.48 143.28 47.7 ;
        RECT  132.94 46.34 143.28 46.48 ;
        RECT  12.12 46.34 130.94 46.48 ;
        RECT  0.595 46.34 10.12 46.48 ;
        RECT  132.94 46 143.28 46.34 ;
        RECT  12.12 46 130.94 46.34 ;
        RECT  0 46 10.12 46.34 ;
        RECT  0 45.8 143.28 46 ;
        RECT  0 45.66 142.685 45.8 ;
        RECT  0 44.44 143.28 45.66 ;
        RECT  0.595 44.3 143.28 44.44 ;
        RECT  0 43.76 143.28 44.3 ;
        RECT  133.05 43.62 142.685 43.76 ;
        RECT  12.12 43.62 131.05 43.76 ;
        RECT  0 43.62 10.12 43.76 ;
        RECT  133.05 43.28 143.28 43.62 ;
        RECT  12.12 43.28 131.05 43.62 ;
        RECT  0 43.28 10.12 43.62 ;
        RECT  0 42.4 143.28 43.28 ;
        RECT  0.595 42.26 143.28 42.4 ;
        RECT  0 41.72 143.28 42.26 ;
        RECT  0 41.58 142.685 41.72 ;
        RECT  0 41.04 143.28 41.58 ;
        RECT  132.94 40.56 143.28 41.04 ;
        RECT  12.12 40.56 130.94 41.04 ;
        RECT  0 40.56 10.12 41.04 ;
        RECT  0 40.36 143.28 40.56 ;
        RECT  0.595 40.22 143.28 40.36 ;
        RECT  0 39.68 143.28 40.22 ;
        RECT  0 39.54 142.685 39.68 ;
        RECT  0 38.32 143.28 39.54 ;
        RECT  133.05 38.18 143.28 38.32 ;
        RECT  12.12 38.18 131.05 38.32 ;
        RECT  0.595 38.18 10.12 38.32 ;
        RECT  133.05 37.84 143.28 38.18 ;
        RECT  12.12 37.84 131.05 38.18 ;
        RECT  0 37.84 10.12 38.18 ;
        RECT  0 37.64 143.28 37.84 ;
        RECT  0 37.5 142.685 37.64 ;
        RECT  0 36.28 143.28 37.5 ;
        RECT  0.595 36.14 143.28 36.28 ;
        RECT  0 35.6 143.28 36.14 ;
        RECT  132.94 35.46 142.685 35.6 ;
        RECT  12.12 35.46 130.94 35.6 ;
        RECT  0 35.46 10.12 35.6 ;
        RECT  132.94 35.12 143.28 35.46 ;
        RECT  12.12 35.12 130.94 35.46 ;
        RECT  0 35.12 10.12 35.46 ;
        RECT  0 34.24 143.28 35.12 ;
        RECT  0.595 34.1 143.28 34.24 ;
        RECT  0 33.56 143.28 34.1 ;
        RECT  0 33.42 142.685 33.56 ;
        RECT  0 32.88 143.28 33.42 ;
        RECT  133.05 32.74 143.28 32.88 ;
        RECT  12.12 32.74 131.05 32.88 ;
        RECT  0.595 32.74 10.12 32.88 ;
        RECT  133.05 32.4 143.28 32.74 ;
        RECT  12.12 32.4 131.05 32.74 ;
        RECT  0 32.4 10.12 32.74 ;
        RECT  0 31.52 143.28 32.4 ;
        RECT  0 31.38 142.685 31.52 ;
        RECT  0 30.84 143.28 31.38 ;
        RECT  0.595 30.7 143.28 30.84 ;
        RECT  0 30.16 143.28 30.7 ;
        RECT  132.94 29.68 143.28 30.16 ;
        RECT  12.12 29.68 130.94 30.16 ;
        RECT  0 29.68 10.12 30.16 ;
        RECT  0 29.48 143.28 29.68 ;
        RECT  0 29.34 142.685 29.48 ;
        RECT  0 28.8 143.28 29.34 ;
        RECT  0.595 28.66 143.28 28.8 ;
        RECT  0 27.44 143.28 28.66 ;
        RECT  133.05 27.3 142.685 27.44 ;
        RECT  12.12 27.3 131.05 27.44 ;
        RECT  0 27.3 10.12 27.44 ;
        RECT  133.05 26.96 143.28 27.3 ;
        RECT  12.12 26.96 131.05 27.3 ;
        RECT  0 26.96 10.12 27.3 ;
        RECT  0 26.76 143.28 26.96 ;
        RECT  0.595 26.62 143.28 26.76 ;
        RECT  0 26.08 143.28 26.62 ;
        RECT  0 25.94 142.685 26.08 ;
        RECT  0 24.72 143.28 25.94 ;
        RECT  132.94 24.58 143.28 24.72 ;
        RECT  12.12 24.58 130.94 24.72 ;
        RECT  0.595 24.58 10.12 24.72 ;
        RECT  132.94 24.24 143.28 24.58 ;
        RECT  12.12 24.24 130.94 24.58 ;
        RECT  0 24.24 10.12 24.58 ;
        RECT  0 24.04 143.28 24.24 ;
        RECT  0 23.9 142.685 24.04 ;
        RECT  0 22.68 143.28 23.9 ;
        RECT  0.595 22.54 143.28 22.68 ;
        RECT  0 22 143.28 22.54 ;
        RECT  133.05 21.86 142.685 22 ;
        RECT  12.12 21.86 131.05 22 ;
        RECT  0 21.86 10.12 22 ;
        RECT  133.05 21.52 143.28 21.86 ;
        RECT  12.12 21.52 131.05 21.86 ;
        RECT  0 21.52 10.12 21.86 ;
        RECT  0 20.64 143.28 21.52 ;
        RECT  0.595 20.5 143.28 20.64 ;
        RECT  0 19.96 143.28 20.5 ;
        RECT  0 19.82 142.685 19.96 ;
        RECT  0 19.28 143.28 19.82 ;
        RECT  132.94 18.8 143.28 19.28 ;
        RECT  12.12 18.8 130.94 19.28 ;
        RECT  0 18.8 10.12 19.28 ;
        RECT  0 18.6 143.28 18.8 ;
        RECT  0.595 18.46 143.28 18.6 ;
        RECT  0 17.92 143.28 18.46 ;
        RECT  0 17.78 142.685 17.92 ;
        RECT  0 16.56 143.28 17.78 ;
        RECT  133.05 16.42 143.28 16.56 ;
        RECT  12.12 16.42 131.05 16.56 ;
        RECT  0.595 16.42 10.12 16.56 ;
        RECT  133.05 16.08 143.28 16.42 ;
        RECT  12.12 16.08 131.05 16.42 ;
        RECT  0 16.08 10.12 16.42 ;
        RECT  0 15.88 143.28 16.08 ;
        RECT  0 15.74 142.685 15.88 ;
        RECT  0 14.52 143.28 15.74 ;
        RECT  0.595 14.38 143.28 14.52 ;
        RECT  0 13.84 143.28 14.38 ;
        RECT  132.94 13.7 142.685 13.84 ;
        RECT  12.12 13.7 130.94 13.84 ;
        RECT  0 13.7 10.12 13.84 ;
        RECT  132.94 13.36 143.28 13.7 ;
        RECT  12.12 13.36 130.94 13.7 ;
        RECT  0 13.36 10.12 13.7 ;
        RECT  0 12.48 143.28 13.36 ;
        RECT  0.595 12.34 143.28 12.48 ;
        RECT  0 11.8 143.28 12.34 ;
        RECT  0 11.66 142.685 11.8 ;
        RECT  0 11.12 143.28 11.66 ;
        RECT  133.05 10.64 143.28 11.12 ;
        RECT  0 10.64 10.12 11.12 ;
        RECT  0 10.44 143.28 10.64 ;
        RECT  0.595 10.3 143.28 10.44 ;
        RECT  0 9.76 143.28 10.3 ;
        RECT  0 9.62 142.685 9.76 ;
        RECT  0 8.4 143.28 9.62 ;
        RECT  0.595 8.26 143.28 8.4 ;
        RECT  0 7.72 143.28 8.26 ;
        RECT  0 7.58 142.685 7.72 ;
        RECT  0 6.36 143.28 7.58 ;
        RECT  0.595 6.22 143.28 6.36 ;
        RECT  0 5.68 143.28 6.22 ;
        RECT  0 5.54 142.685 5.68 ;
        RECT  0 4.32 143.28 5.54 ;
        RECT  0.595 4.18 143.28 4.32 ;
        RECT  0 3.64 143.28 4.18 ;
        RECT  0 3.5 142.685 3.64 ;
        RECT  0 2.28 143.28 3.5 ;
        RECT  0.595 2.14 143.28 2.28 ;
        RECT  0 1.6 143.28 2.14 ;
        RECT  0 1.46 142.685 1.6 ;
        RECT  0 0 143.28 1.46 ;
      LAYER li1 ;
        RECT  0 0 143.28 143.28 ;
    END
END ember_ram_slave
END LIBRARY
